VERSION 5.8 ;
BUSBITCHARS "[]" ;
DIVIDERCHAR "/" ;
UNITS
    DATABASE MICRONS 1000 ;
END UNITS

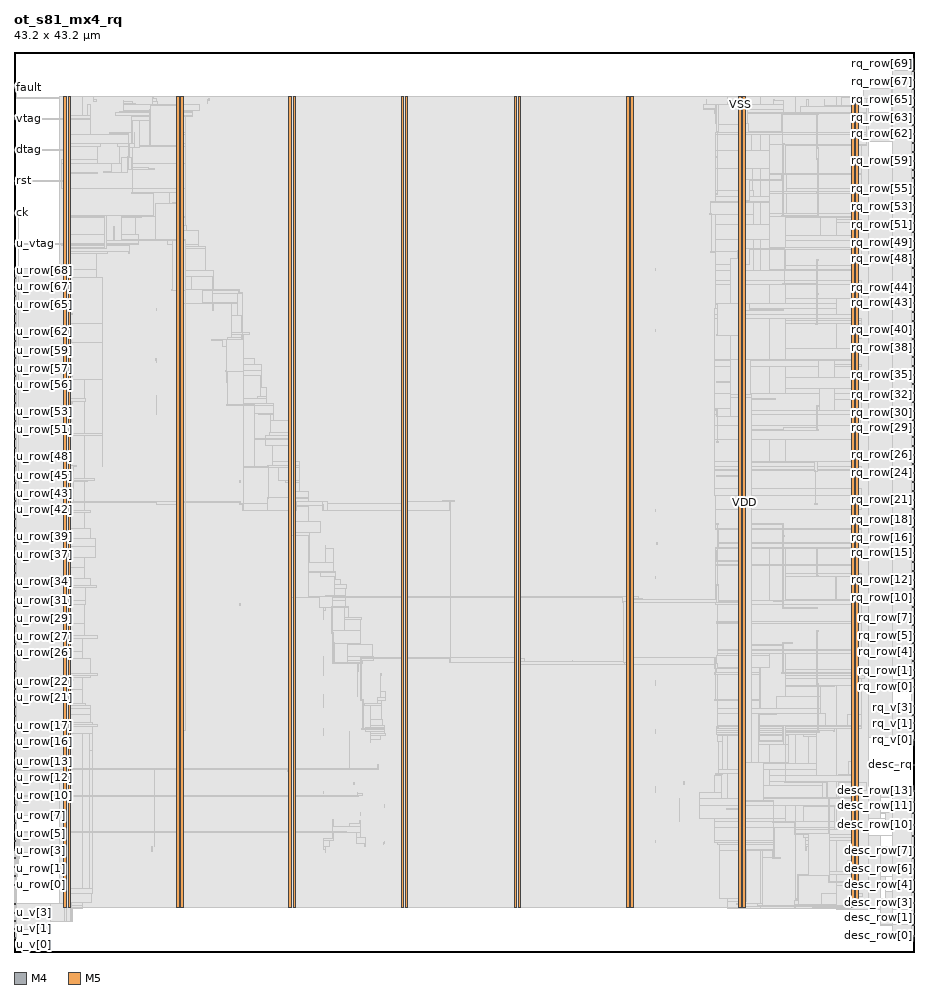
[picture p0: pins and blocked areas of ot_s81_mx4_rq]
MACRO ot_s81_mx4_rq
  FOREIGN ot_s81_mx4_rq 0 0 ;
  CLASS BLOCK ;
  SIZE 43.2 BY 43.2 ;
  PIN ck
    DIRECTION INPUT ;
    USE SIGNAL ;
    PORT
      LAYER M4 ;
        RECT  0 35.472 0.084 35.496 ;
    END
  END ck
  PIN desc_row[0]
    DIRECTION INPUT ;
    USE SIGNAL ;
    PORT
      LAYER M4 ;
        RECT  43.116 0.768 43.2 0.792 ;
    END
  END desc_row[0]
  PIN desc_row[10]
    DIRECTION INPUT ;
    USE SIGNAL ;
    PORT
      LAYER M4 ;
        RECT  43.116 6.096 43.2 6.12 ;
    END
  END desc_row[10]
  PIN desc_row[11]
    DIRECTION INPUT ;
    USE SIGNAL ;
    PORT
      LAYER M4 ;
        RECT  43.116 6.672 43.2 6.696 ;
    END
  END desc_row[11]
  PIN desc_row[12]
    DIRECTION INPUT ;
    USE SIGNAL ;
    PORT
      LAYER M4 ;
        RECT  43.116 7.2 43.2 7.224 ;
    END
  END desc_row[12]
  PIN desc_row[13]
    DIRECTION INPUT ;
    USE SIGNAL ;
    PORT
      LAYER M4 ;
        RECT  43.116 7.728 43.2 7.752 ;
    END
  END desc_row[13]
  PIN desc_row[1]
    DIRECTION INPUT ;
    USE SIGNAL ;
    PORT
      LAYER M4 ;
        RECT  43.116 1.296 43.2 1.32 ;
    END
  END desc_row[1]
  PIN desc_row[2]
    DIRECTION INPUT ;
    USE SIGNAL ;
    PORT
      LAYER M4 ;
        RECT  43.116 1.824 43.2 1.848 ;
    END
  END desc_row[2]
  PIN desc_row[3]
    DIRECTION INPUT ;
    USE SIGNAL ;
    PORT
      LAYER M4 ;
        RECT  43.116 2.352 43.2 2.376 ;
    END
  END desc_row[3]
  PIN desc_row[4]
    DIRECTION INPUT ;
    USE SIGNAL ;
    PORT
      LAYER M4 ;
        RECT  43.116 2.88 43.2 2.904 ;
    END
  END desc_row[4]
  PIN desc_row[5]
    DIRECTION INPUT ;
    USE SIGNAL ;
    PORT
      LAYER M4 ;
        RECT  43.116 3.456 43.2 3.48 ;
    END
  END desc_row[5]
  PIN desc_row[6]
    DIRECTION INPUT ;
    USE SIGNAL ;
    PORT
      LAYER M4 ;
        RECT  43.116 3.984 43.2 4.008 ;
    END
  END desc_row[6]
  PIN desc_row[7]
    DIRECTION INPUT ;
    USE SIGNAL ;
    PORT
      LAYER M4 ;
        RECT  43.116 4.512 43.2 4.536 ;
    END
  END desc_row[7]
  PIN desc_row[8]
    DIRECTION INPUT ;
    USE SIGNAL ;
    PORT
      LAYER M4 ;
        RECT  43.116 5.04 43.2 5.064 ;
    END
  END desc_row[8]
  PIN desc_row[9]
    DIRECTION INPUT ;
    USE SIGNAL ;
    PORT
      LAYER M4 ;
        RECT  43.116 5.568 43.2 5.592 ;
    END
  END desc_row[9]
  PIN desc_rq
    DIRECTION INPUT ;
    USE SIGNAL ;
    PORT
      LAYER M4 ;
        RECT  43.116 8.976 43.2 9 ;
    END
  END desc_rq
  PIN dtag
    DIRECTION OUTPUT ;
    USE SIGNAL ;
    PORT
      LAYER M4 ;
        RECT  0 38.496 0.084 38.52 ;
    END
  END dtag
  PIN fault
    DIRECTION OUTPUT ;
    USE SIGNAL ;
    PORT
      LAYER M4 ;
        RECT  0 41.472 0.084 41.496 ;
    END
  END fault
  PIN rq_row[0]
    DIRECTION OUTPUT ;
    USE SIGNAL ;
    PORT
      LAYER M4 ;
        RECT  43.116 12.72 43.2 12.744 ;
    END
  END rq_row[0]
  PIN rq_row[10]
    DIRECTION OUTPUT ;
    USE SIGNAL ;
    PORT
      LAYER M4 ;
        RECT  43.116 16.992 43.2 17.016 ;
    END
  END rq_row[10]
  PIN rq_row[11]
    DIRECTION OUTPUT ;
    USE SIGNAL ;
    PORT
      LAYER M4 ;
        RECT  43.116 17.424 43.2 17.448 ;
    END
  END rq_row[11]
  PIN rq_row[12]
    DIRECTION OUTPUT ;
    USE SIGNAL ;
    PORT
      LAYER M4 ;
        RECT  43.116 17.856 43.2 17.88 ;
    END
  END rq_row[12]
  PIN rq_row[13]
    DIRECTION OUTPUT ;
    USE SIGNAL ;
    PORT
      LAYER M4 ;
        RECT  43.116 18.288 43.2 18.312 ;
    END
  END rq_row[13]
  PIN rq_row[14]
    DIRECTION OUTPUT ;
    USE SIGNAL ;
    PORT
      LAYER M4 ;
        RECT  43.116 18.72 43.2 18.744 ;
    END
  END rq_row[14]
  PIN rq_row[15]
    DIRECTION OUTPUT ;
    USE SIGNAL ;
    PORT
      LAYER M4 ;
        RECT  43.116 19.152 43.2 19.176 ;
    END
  END rq_row[15]
  PIN rq_row[16]
    DIRECTION OUTPUT ;
    USE SIGNAL ;
    PORT
      LAYER M4 ;
        RECT  43.116 19.536 43.2 19.56 ;
    END
  END rq_row[16]
  PIN rq_row[17]
    DIRECTION OUTPUT ;
    USE SIGNAL ;
    PORT
      LAYER M4 ;
        RECT  43.116 19.968 43.2 19.992 ;
    END
  END rq_row[17]
  PIN rq_row[18]
    DIRECTION OUTPUT ;
    USE SIGNAL ;
    PORT
      LAYER M4 ;
        RECT  43.116 20.4 43.2 20.424 ;
    END
  END rq_row[18]
  PIN rq_row[19]
    DIRECTION OUTPUT ;
    USE SIGNAL ;
    PORT
      LAYER M4 ;
        RECT  43.116 20.832 43.2 20.856 ;
    END
  END rq_row[19]
  PIN rq_row[1]
    DIRECTION OUTPUT ;
    USE SIGNAL ;
    PORT
      LAYER M4 ;
        RECT  43.116 13.152 43.2 13.176 ;
    END
  END rq_row[1]
  PIN rq_row[20]
    DIRECTION OUTPUT ;
    USE SIGNAL ;
    PORT
      LAYER M4 ;
        RECT  43.116 21.264 43.2 21.288 ;
    END
  END rq_row[20]
  PIN rq_row[21]
    DIRECTION OUTPUT ;
    USE SIGNAL ;
    PORT
      LAYER M4 ;
        RECT  43.116 21.696 43.2 21.72 ;
    END
  END rq_row[21]
  PIN rq_row[22]
    DIRECTION OUTPUT ;
    USE SIGNAL ;
    PORT
      LAYER M4 ;
        RECT  43.116 22.128 43.2 22.152 ;
    END
  END rq_row[22]
  PIN rq_row[23]
    DIRECTION OUTPUT ;
    USE SIGNAL ;
    PORT
      LAYER M4 ;
        RECT  43.116 22.56 43.2 22.584 ;
    END
  END rq_row[23]
  PIN rq_row[24]
    DIRECTION OUTPUT ;
    USE SIGNAL ;
    PORT
      LAYER M4 ;
        RECT  43.116 22.992 43.2 23.016 ;
    END
  END rq_row[24]
  PIN rq_row[25]
    DIRECTION OUTPUT ;
    USE SIGNAL ;
    PORT
      LAYER M4 ;
        RECT  43.116 23.424 43.2 23.448 ;
    END
  END rq_row[25]
  PIN rq_row[26]
    DIRECTION OUTPUT ;
    USE SIGNAL ;
    PORT
      LAYER M4 ;
        RECT  43.116 23.856 43.2 23.88 ;
    END
  END rq_row[26]
  PIN rq_row[27]
    DIRECTION OUTPUT ;
    USE SIGNAL ;
    PORT
      LAYER M4 ;
        RECT  43.116 24.288 43.2 24.312 ;
    END
  END rq_row[27]
  PIN rq_row[28]
    DIRECTION OUTPUT ;
    USE SIGNAL ;
    PORT
      LAYER M4 ;
        RECT  43.116 24.72 43.2 24.744 ;
    END
  END rq_row[28]
  PIN rq_row[29]
    DIRECTION OUTPUT ;
    USE SIGNAL ;
    PORT
      LAYER M4 ;
        RECT  43.116 25.152 43.2 25.176 ;
    END
  END rq_row[29]
  PIN rq_row[2]
    DIRECTION OUTPUT ;
    USE SIGNAL ;
    PORT
      LAYER M4 ;
        RECT  43.116 13.536 43.2 13.56 ;
    END
  END rq_row[2]
  PIN rq_row[30]
    DIRECTION OUTPUT ;
    USE SIGNAL ;
    PORT
      LAYER M4 ;
        RECT  43.116 25.536 43.2 25.56 ;
    END
  END rq_row[30]
  PIN rq_row[31]
    DIRECTION OUTPUT ;
    USE SIGNAL ;
    PORT
      LAYER M4 ;
        RECT  43.116 25.968 43.2 25.992 ;
    END
  END rq_row[31]
  PIN rq_row[32]
    DIRECTION OUTPUT ;
    USE SIGNAL ;
    PORT
      LAYER M4 ;
        RECT  43.116 26.4 43.2 26.424 ;
    END
  END rq_row[32]
  PIN rq_row[33]
    DIRECTION OUTPUT ;
    USE SIGNAL ;
    PORT
      LAYER M4 ;
        RECT  43.116 26.832 43.2 26.856 ;
    END
  END rq_row[33]
  PIN rq_row[34]
    DIRECTION OUTPUT ;
    USE SIGNAL ;
    PORT
      LAYER M4 ;
        RECT  43.116 27.264 43.2 27.288 ;
    END
  END rq_row[34]
  PIN rq_row[35]
    DIRECTION OUTPUT ;
    USE SIGNAL ;
    PORT
      LAYER M4 ;
        RECT  43.116 27.696 43.2 27.72 ;
    END
  END rq_row[35]
  PIN rq_row[36]
    DIRECTION OUTPUT ;
    USE SIGNAL ;
    PORT
      LAYER M4 ;
        RECT  43.116 28.128 43.2 28.152 ;
    END
  END rq_row[36]
  PIN rq_row[37]
    DIRECTION OUTPUT ;
    USE SIGNAL ;
    PORT
      LAYER M4 ;
        RECT  43.116 28.56 43.2 28.584 ;
    END
  END rq_row[37]
  PIN rq_row[38]
    DIRECTION OUTPUT ;
    USE SIGNAL ;
    PORT
      LAYER M4 ;
        RECT  43.116 28.992 43.2 29.016 ;
    END
  END rq_row[38]
  PIN rq_row[39]
    DIRECTION OUTPUT ;
    USE SIGNAL ;
    PORT
      LAYER M4 ;
        RECT  43.116 29.424 43.2 29.448 ;
    END
  END rq_row[39]
  PIN rq_row[3]
    DIRECTION OUTPUT ;
    USE SIGNAL ;
    PORT
      LAYER M4 ;
        RECT  43.116 13.968 43.2 13.992 ;
    END
  END rq_row[3]
  PIN rq_row[40]
    DIRECTION OUTPUT ;
    USE SIGNAL ;
    PORT
      LAYER M4 ;
        RECT  43.116 29.856 43.2 29.88 ;
    END
  END rq_row[40]
  PIN rq_row[41]
    DIRECTION OUTPUT ;
    USE SIGNAL ;
    PORT
      LAYER M4 ;
        RECT  43.116 30.288 43.2 30.312 ;
    END
  END rq_row[41]
  PIN rq_row[42]
    DIRECTION OUTPUT ;
    USE SIGNAL ;
    PORT
      LAYER M4 ;
        RECT  43.116 30.72 43.2 30.744 ;
    END
  END rq_row[42]
  PIN rq_row[43]
    DIRECTION OUTPUT ;
    USE SIGNAL ;
    PORT
      LAYER M4 ;
        RECT  43.116 31.152 43.2 31.176 ;
    END
  END rq_row[43]
  PIN rq_row[44]
    DIRECTION OUTPUT ;
    USE SIGNAL ;
    PORT
      LAYER M4 ;
        RECT  43.116 31.536 43.2 31.56 ;
    END
  END rq_row[44]
  PIN rq_row[45]
    DIRECTION OUTPUT ;
    USE SIGNAL ;
    PORT
      LAYER M4 ;
        RECT  43.116 31.968 43.2 31.992 ;
    END
  END rq_row[45]
  PIN rq_row[46]
    DIRECTION OUTPUT ;
    USE SIGNAL ;
    PORT
      LAYER M4 ;
        RECT  43.116 32.4 43.2 32.424 ;
    END
  END rq_row[46]
  PIN rq_row[47]
    DIRECTION OUTPUT ;
    USE SIGNAL ;
    PORT
      LAYER M4 ;
        RECT  43.116 32.832 43.2 32.856 ;
    END
  END rq_row[47]
  PIN rq_row[48]
    DIRECTION OUTPUT ;
    USE SIGNAL ;
    PORT
      LAYER M4 ;
        RECT  43.116 33.264 43.2 33.288 ;
    END
  END rq_row[48]
  PIN rq_row[49]
    DIRECTION OUTPUT ;
    USE SIGNAL ;
    PORT
      LAYER M4 ;
        RECT  43.116 33.696 43.2 33.72 ;
    END
  END rq_row[49]
  PIN rq_row[4]
    DIRECTION OUTPUT ;
    USE SIGNAL ;
    PORT
      LAYER M4 ;
        RECT  43.116 14.4 43.2 14.424 ;
    END
  END rq_row[4]
  PIN rq_row[50]
    DIRECTION OUTPUT ;
    USE SIGNAL ;
    PORT
      LAYER M4 ;
        RECT  43.116 34.128 43.2 34.152 ;
    END
  END rq_row[50]
  PIN rq_row[51]
    DIRECTION OUTPUT ;
    USE SIGNAL ;
    PORT
      LAYER M4 ;
        RECT  43.116 34.56 43.2 34.584 ;
    END
  END rq_row[51]
  PIN rq_row[52]
    DIRECTION OUTPUT ;
    USE SIGNAL ;
    PORT
      LAYER M4 ;
        RECT  43.116 34.992 43.2 35.016 ;
    END
  END rq_row[52]
  PIN rq_row[53]
    DIRECTION OUTPUT ;
    USE SIGNAL ;
    PORT
      LAYER M4 ;
        RECT  43.116 35.424 43.2 35.448 ;
    END
  END rq_row[53]
  PIN rq_row[54]
    DIRECTION OUTPUT ;
    USE SIGNAL ;
    PORT
      LAYER M4 ;
        RECT  43.116 35.856 43.2 35.88 ;
    END
  END rq_row[54]
  PIN rq_row[55]
    DIRECTION OUTPUT ;
    USE SIGNAL ;
    PORT
      LAYER M4 ;
        RECT  43.116 36.288 43.2 36.312 ;
    END
  END rq_row[55]
  PIN rq_row[56]
    DIRECTION OUTPUT ;
    USE SIGNAL ;
    PORT
      LAYER M4 ;
        RECT  43.116 36.72 43.2 36.744 ;
    END
  END rq_row[56]
  PIN rq_row[57]
    DIRECTION OUTPUT ;
    USE SIGNAL ;
    PORT
      LAYER M4 ;
        RECT  43.116 37.152 43.2 37.176 ;
    END
  END rq_row[57]
  PIN rq_row[58]
    DIRECTION OUTPUT ;
    USE SIGNAL ;
    PORT
      LAYER M4 ;
        RECT  43.116 37.536 43.2 37.56 ;
    END
  END rq_row[58]
  PIN rq_row[59]
    DIRECTION OUTPUT ;
    USE SIGNAL ;
    PORT
      LAYER M4 ;
        RECT  43.116 37.968 43.2 37.992 ;
    END
  END rq_row[59]
  PIN rq_row[5]
    DIRECTION OUTPUT ;
    USE SIGNAL ;
    PORT
      LAYER M4 ;
        RECT  43.116 14.832 43.2 14.856 ;
    END
  END rq_row[5]
  PIN rq_row[60]
    DIRECTION OUTPUT ;
    USE SIGNAL ;
    PORT
      LAYER M4 ;
        RECT  43.116 38.4 43.2 38.424 ;
    END
  END rq_row[60]
  PIN rq_row[61]
    DIRECTION OUTPUT ;
    USE SIGNAL ;
    PORT
      LAYER M4 ;
        RECT  43.116 38.832 43.2 38.856 ;
    END
  END rq_row[61]
  PIN rq_row[62]
    DIRECTION OUTPUT ;
    USE SIGNAL ;
    PORT
      LAYER M4 ;
        RECT  43.116 39.264 43.2 39.288 ;
    END
  END rq_row[62]
  PIN rq_row[63]
    DIRECTION OUTPUT ;
    USE SIGNAL ;
    PORT
      LAYER M4 ;
        RECT  43.116 39.696 43.2 39.72 ;
    END
  END rq_row[63]
  PIN rq_row[64]
    DIRECTION OUTPUT ;
    USE SIGNAL ;
    PORT
      LAYER M4 ;
        RECT  43.116 40.128 43.2 40.152 ;
    END
  END rq_row[64]
  PIN rq_row[65]
    DIRECTION OUTPUT ;
    USE SIGNAL ;
    PORT
      LAYER M4 ;
        RECT  43.116 40.56 43.2 40.584 ;
    END
  END rq_row[65]
  PIN rq_row[66]
    DIRECTION OUTPUT ;
    USE SIGNAL ;
    PORT
      LAYER M4 ;
        RECT  43.116 40.992 43.2 41.016 ;
    END
  END rq_row[66]
  PIN rq_row[67]
    DIRECTION OUTPUT ;
    USE SIGNAL ;
    PORT
      LAYER M4 ;
        RECT  43.116 41.424 43.2 41.448 ;
    END
  END rq_row[67]
  PIN rq_row[68]
    DIRECTION OUTPUT ;
    USE SIGNAL ;
    PORT
      LAYER M4 ;
        RECT  43.116 41.856 43.2 41.88 ;
    END
  END rq_row[68]
  PIN rq_row[69]
    DIRECTION OUTPUT ;
    USE SIGNAL ;
    PORT
      LAYER M4 ;
        RECT  43.116 42.288 43.2 42.312 ;
    END
  END rq_row[69]
  PIN rq_row[6]
    DIRECTION OUTPUT ;
    USE SIGNAL ;
    PORT
      LAYER M4 ;
        RECT  43.116 15.264 43.2 15.288 ;
    END
  END rq_row[6]
  PIN rq_row[7]
    DIRECTION OUTPUT ;
    USE SIGNAL ;
    PORT
      LAYER M4 ;
        RECT  43.116 15.696 43.2 15.72 ;
    END
  END rq_row[7]
  PIN rq_row[8]
    DIRECTION OUTPUT ;
    USE SIGNAL ;
    PORT
      LAYER M4 ;
        RECT  43.116 16.128 43.2 16.152 ;
    END
  END rq_row[8]
  PIN rq_row[9]
    DIRECTION OUTPUT ;
    USE SIGNAL ;
    PORT
      LAYER M4 ;
        RECT  43.116 16.56 43.2 16.584 ;
    END
  END rq_row[9]
  PIN rq_v[0]
    DIRECTION OUTPUT ;
    USE SIGNAL ;
    PORT
      LAYER M4 ;
        RECT  43.116 10.176 43.2 10.2 ;
    END
  END rq_v[0]
  PIN rq_v[1]
    DIRECTION OUTPUT ;
    USE SIGNAL ;
    PORT
      LAYER M4 ;
        RECT  43.116 10.608 43.2 10.632 ;
    END
  END rq_v[1]
  PIN rq_v[2]
    DIRECTION OUTPUT ;
    USE SIGNAL ;
    PORT
      LAYER M4 ;
        RECT  43.116 10.992 43.2 11.016 ;
    END
  END rq_v[2]
  PIN rq_v[3]
    DIRECTION OUTPUT ;
    USE SIGNAL ;
    PORT
      LAYER M4 ;
        RECT  43.116 11.376 43.2 11.4 ;
    END
  END rq_v[3]
  PIN rq_v[4]
    DIRECTION OUTPUT ;
    USE SIGNAL ;
    PORT
      LAYER M4 ;
        RECT  43.116 11.808 43.2 11.832 ;
    END
  END rq_v[4]
  PIN rst
    DIRECTION INPUT ;
    USE SIGNAL ;
    PORT
      LAYER M4 ;
        RECT  0 37.008 0.084 37.032 ;
    END
  END rst
  PIN u_row[0]
    DIRECTION INPUT ;
    USE SIGNAL ;
    PORT
      LAYER M4 ;
        RECT  0 3.216 0.084 3.24 ;
    END
  END u_row[0]
  PIN u_row[10]
    DIRECTION INPUT ;
    USE SIGNAL ;
    PORT
      LAYER M4 ;
        RECT  0 7.488 0.084 7.512 ;
    END
  END u_row[10]
  PIN u_row[11]
    DIRECTION INPUT ;
    USE SIGNAL ;
    PORT
      LAYER M4 ;
        RECT  0 7.92 0.084 7.944 ;
    END
  END u_row[11]
  PIN u_row[12]
    DIRECTION INPUT ;
    USE SIGNAL ;
    PORT
      LAYER M4 ;
        RECT  0 8.352 0.084 8.376 ;
    END
  END u_row[12]
  PIN u_row[13]
    DIRECTION INPUT ;
    USE SIGNAL ;
    PORT
      LAYER M4 ;
        RECT  0 8.784 0.084 8.808 ;
    END
  END u_row[13]
  PIN u_row[14]
    DIRECTION INPUT ;
    USE SIGNAL ;
    PORT
      LAYER M4 ;
        RECT  0 9.216 0.084 9.24 ;
    END
  END u_row[14]
  PIN u_row[15]
    DIRECTION INPUT ;
    USE SIGNAL ;
    PORT
      LAYER M4 ;
        RECT  0 9.648 0.084 9.672 ;
    END
  END u_row[15]
  PIN u_row[16]
    DIRECTION INPUT ;
    USE SIGNAL ;
    PORT
      LAYER M4 ;
        RECT  0 10.08 0.084 10.104 ;
    END
  END u_row[16]
  PIN u_row[17]
    DIRECTION INPUT ;
    USE SIGNAL ;
    PORT
      LAYER M4 ;
        RECT  0 10.512 0.084 10.536 ;
    END
  END u_row[17]
  PIN u_row[18]
    DIRECTION INPUT ;
    USE SIGNAL ;
    PORT
      LAYER M4 ;
        RECT  0 10.896 0.084 10.92 ;
    END
  END u_row[18]
  PIN u_row[19]
    DIRECTION INPUT ;
    USE SIGNAL ;
    PORT
      LAYER M4 ;
        RECT  0 11.328 0.084 11.352 ;
    END
  END u_row[19]
  PIN u_row[1]
    DIRECTION INPUT ;
    USE SIGNAL ;
    PORT
      LAYER M4 ;
        RECT  0 3.648 0.084 3.672 ;
    END
  END u_row[1]
  PIN u_row[20]
    DIRECTION INPUT ;
    USE SIGNAL ;
    PORT
      LAYER M4 ;
        RECT  0 11.76 0.084 11.784 ;
    END
  END u_row[20]
  PIN u_row[21]
    DIRECTION INPUT ;
    USE SIGNAL ;
    PORT
      LAYER M4 ;
        RECT  0 12.192 0.084 12.216 ;
    END
  END u_row[21]
  PIN u_row[22]
    DIRECTION INPUT ;
    USE SIGNAL ;
    PORT
      LAYER M4 ;
        RECT  0 12.624 0.084 12.648 ;
    END
  END u_row[22]
  PIN u_row[23]
    DIRECTION INPUT ;
    USE SIGNAL ;
    PORT
      LAYER M4 ;
        RECT  0 13.056 0.084 13.08 ;
    END
  END u_row[23]
  PIN u_row[24]
    DIRECTION INPUT ;
    USE SIGNAL ;
    PORT
      LAYER M4 ;
        RECT  0 13.488 0.084 13.512 ;
    END
  END u_row[24]
  PIN u_row[25]
    DIRECTION INPUT ;
    USE SIGNAL ;
    PORT
      LAYER M4 ;
        RECT  0 13.92 0.084 13.944 ;
    END
  END u_row[25]
  PIN u_row[26]
    DIRECTION INPUT ;
    USE SIGNAL ;
    PORT
      LAYER M4 ;
        RECT  0 14.352 0.084 14.376 ;
    END
  END u_row[26]
  PIN u_row[27]
    DIRECTION INPUT ;
    USE SIGNAL ;
    PORT
      LAYER M4 ;
        RECT  0 14.784 0.084 14.808 ;
    END
  END u_row[27]
  PIN u_row[28]
    DIRECTION INPUT ;
    USE SIGNAL ;
    PORT
      LAYER M4 ;
        RECT  0 15.216 0.084 15.24 ;
    END
  END u_row[28]
  PIN u_row[29]
    DIRECTION INPUT ;
    USE SIGNAL ;
    PORT
      LAYER M4 ;
        RECT  0 15.648 0.084 15.672 ;
    END
  END u_row[29]
  PIN u_row[2]
    DIRECTION INPUT ;
    USE SIGNAL ;
    PORT
      LAYER M4 ;
        RECT  0 4.08 0.084 4.104 ;
    END
  END u_row[2]
  PIN u_row[30]
    DIRECTION INPUT ;
    USE SIGNAL ;
    PORT
      LAYER M4 ;
        RECT  0 16.08 0.084 16.104 ;
    END
  END u_row[30]
  PIN u_row[31]
    DIRECTION INPUT ;
    USE SIGNAL ;
    PORT
      LAYER M4 ;
        RECT  0 16.512 0.084 16.536 ;
    END
  END u_row[31]
  PIN u_row[32]
    DIRECTION INPUT ;
    USE SIGNAL ;
    PORT
      LAYER M4 ;
        RECT  0 16.896 0.084 16.92 ;
    END
  END u_row[32]
  PIN u_row[33]
    DIRECTION INPUT ;
    USE SIGNAL ;
    PORT
      LAYER M4 ;
        RECT  0 17.328 0.084 17.352 ;
    END
  END u_row[33]
  PIN u_row[34]
    DIRECTION INPUT ;
    USE SIGNAL ;
    PORT
      LAYER M4 ;
        RECT  0 17.76 0.084 17.784 ;
    END
  END u_row[34]
  PIN u_row[35]
    DIRECTION INPUT ;
    USE SIGNAL ;
    PORT
      LAYER M4 ;
        RECT  0 18.192 0.084 18.216 ;
    END
  END u_row[35]
  PIN u_row[36]
    DIRECTION INPUT ;
    USE SIGNAL ;
    PORT
      LAYER M4 ;
        RECT  0 18.624 0.084 18.648 ;
    END
  END u_row[36]
  PIN u_row[37]
    DIRECTION INPUT ;
    USE SIGNAL ;
    PORT
      LAYER M4 ;
        RECT  0 19.056 0.084 19.08 ;
    END
  END u_row[37]
  PIN u_row[38]
    DIRECTION INPUT ;
    USE SIGNAL ;
    PORT
      LAYER M4 ;
        RECT  0 19.488 0.084 19.512 ;
    END
  END u_row[38]
  PIN u_row[39]
    DIRECTION INPUT ;
    USE SIGNAL ;
    PORT
      LAYER M4 ;
        RECT  0 19.92 0.084 19.944 ;
    END
  END u_row[39]
  PIN u_row[3]
    DIRECTION INPUT ;
    USE SIGNAL ;
    PORT
      LAYER M4 ;
        RECT  0 4.512 0.084 4.536 ;
    END
  END u_row[3]
  PIN u_row[40]
    DIRECTION INPUT ;
    USE SIGNAL ;
    PORT
      LAYER M4 ;
        RECT  0 20.352 0.084 20.376 ;
    END
  END u_row[40]
  PIN u_row[41]
    DIRECTION INPUT ;
    USE SIGNAL ;
    PORT
      LAYER M4 ;
        RECT  0 20.784 0.084 20.808 ;
    END
  END u_row[41]
  PIN u_row[42]
    DIRECTION INPUT ;
    USE SIGNAL ;
    PORT
      LAYER M4 ;
        RECT  0 21.216 0.084 21.24 ;
    END
  END u_row[42]
  PIN u_row[43]
    DIRECTION INPUT ;
    USE SIGNAL ;
    PORT
      LAYER M4 ;
        RECT  0 21.648 0.084 21.672 ;
    END
  END u_row[43]
  PIN u_row[44]
    DIRECTION INPUT ;
    USE SIGNAL ;
    PORT
      LAYER M4 ;
        RECT  0 22.08 0.084 22.104 ;
    END
  END u_row[44]
  PIN u_row[45]
    DIRECTION INPUT ;
    USE SIGNAL ;
    PORT
      LAYER M4 ;
        RECT  0 22.512 0.084 22.536 ;
    END
  END u_row[45]
  PIN u_row[46]
    DIRECTION INPUT ;
    USE SIGNAL ;
    PORT
      LAYER M4 ;
        RECT  0 22.896 0.084 22.92 ;
    END
  END u_row[46]
  PIN u_row[47]
    DIRECTION INPUT ;
    USE SIGNAL ;
    PORT
      LAYER M4 ;
        RECT  0 23.328 0.084 23.352 ;
    END
  END u_row[47]
  PIN u_row[48]
    DIRECTION INPUT ;
    USE SIGNAL ;
    PORT
      LAYER M4 ;
        RECT  0 23.76 0.084 23.784 ;
    END
  END u_row[48]
  PIN u_row[49]
    DIRECTION INPUT ;
    USE SIGNAL ;
    PORT
      LAYER M4 ;
        RECT  0 24.192 0.084 24.216 ;
    END
  END u_row[49]
  PIN u_row[4]
    DIRECTION INPUT ;
    USE SIGNAL ;
    PORT
      LAYER M4 ;
        RECT  0 4.896 0.084 4.92 ;
    END
  END u_row[4]
  PIN u_row[50]
    DIRECTION INPUT ;
    USE SIGNAL ;
    PORT
      LAYER M4 ;
        RECT  0 24.624 0.084 24.648 ;
    END
  END u_row[50]
  PIN u_row[51]
    DIRECTION INPUT ;
    USE SIGNAL ;
    PORT
      LAYER M4 ;
        RECT  0 25.056 0.084 25.08 ;
    END
  END u_row[51]
  PIN u_row[52]
    DIRECTION INPUT ;
    USE SIGNAL ;
    PORT
      LAYER M4 ;
        RECT  0 25.488 0.084 25.512 ;
    END
  END u_row[52]
  PIN u_row[53]
    DIRECTION INPUT ;
    USE SIGNAL ;
    PORT
      LAYER M4 ;
        RECT  0 25.92 0.084 25.944 ;
    END
  END u_row[53]
  PIN u_row[54]
    DIRECTION INPUT ;
    USE SIGNAL ;
    PORT
      LAYER M4 ;
        RECT  0 26.352 0.084 26.376 ;
    END
  END u_row[54]
  PIN u_row[55]
    DIRECTION INPUT ;
    USE SIGNAL ;
    PORT
      LAYER M4 ;
        RECT  0 26.784 0.084 26.808 ;
    END
  END u_row[55]
  PIN u_row[56]
    DIRECTION INPUT ;
    USE SIGNAL ;
    PORT
      LAYER M4 ;
        RECT  0 27.216 0.084 27.24 ;
    END
  END u_row[56]
  PIN u_row[57]
    DIRECTION INPUT ;
    USE SIGNAL ;
    PORT
      LAYER M4 ;
        RECT  0 27.648 0.084 27.672 ;
    END
  END u_row[57]
  PIN u_row[58]
    DIRECTION INPUT ;
    USE SIGNAL ;
    PORT
      LAYER M4 ;
        RECT  0 28.08 0.084 28.104 ;
    END
  END u_row[58]
  PIN u_row[59]
    DIRECTION INPUT ;
    USE SIGNAL ;
    PORT
      LAYER M4 ;
        RECT  0 28.512 0.084 28.536 ;
    END
  END u_row[59]
  PIN u_row[5]
    DIRECTION INPUT ;
    USE SIGNAL ;
    PORT
      LAYER M4 ;
        RECT  0 5.328 0.084 5.352 ;
    END
  END u_row[5]
  PIN u_row[60]
    DIRECTION INPUT ;
    USE SIGNAL ;
    PORT
      LAYER M4 ;
        RECT  0 28.896 0.084 28.92 ;
    END
  END u_row[60]
  PIN u_row[61]
    DIRECTION INPUT ;
    USE SIGNAL ;
    PORT
      LAYER M4 ;
        RECT  0 29.328 0.084 29.352 ;
    END
  END u_row[61]
  PIN u_row[62]
    DIRECTION INPUT ;
    USE SIGNAL ;
    PORT
      LAYER M4 ;
        RECT  0 29.76 0.084 29.784 ;
    END
  END u_row[62]
  PIN u_row[63]
    DIRECTION INPUT ;
    USE SIGNAL ;
    PORT
      LAYER M4 ;
        RECT  0 30.192 0.084 30.216 ;
    END
  END u_row[63]
  PIN u_row[64]
    DIRECTION INPUT ;
    USE SIGNAL ;
    PORT
      LAYER M4 ;
        RECT  0 30.624 0.084 30.648 ;
    END
  END u_row[64]
  PIN u_row[65]
    DIRECTION INPUT ;
    USE SIGNAL ;
    PORT
      LAYER M4 ;
        RECT  0 31.056 0.084 31.08 ;
    END
  END u_row[65]
  PIN u_row[66]
    DIRECTION INPUT ;
    USE SIGNAL ;
    PORT
      LAYER M4 ;
        RECT  0 31.488 0.084 31.512 ;
    END
  END u_row[66]
  PIN u_row[67]
    DIRECTION INPUT ;
    USE SIGNAL ;
    PORT
      LAYER M4 ;
        RECT  0 31.92 0.084 31.944 ;
    END
  END u_row[67]
  PIN u_row[68]
    DIRECTION INPUT ;
    USE SIGNAL ;
    PORT
      LAYER M4 ;
        RECT  0 32.352 0.084 32.376 ;
    END
  END u_row[68]
  PIN u_row[69]
    DIRECTION INPUT ;
    USE SIGNAL ;
    PORT
      LAYER M4 ;
        RECT  0 32.784 0.084 32.808 ;
    END
  END u_row[69]
  PIN u_row[6]
    DIRECTION INPUT ;
    USE SIGNAL ;
    PORT
      LAYER M4 ;
        RECT  0 5.76 0.084 5.784 ;
    END
  END u_row[6]
  PIN u_row[7]
    DIRECTION INPUT ;
    USE SIGNAL ;
    PORT
      LAYER M4 ;
        RECT  0 6.192 0.084 6.216 ;
    END
  END u_row[7]
  PIN u_row[8]
    DIRECTION INPUT ;
    USE SIGNAL ;
    PORT
      LAYER M4 ;
        RECT  0 6.624 0.084 6.648 ;
    END
  END u_row[8]
  PIN u_row[9]
    DIRECTION INPUT ;
    USE SIGNAL ;
    PORT
      LAYER M4 ;
        RECT  0 7.056 0.084 7.08 ;
    END
  END u_row[9]
  PIN u_v[0]
    DIRECTION INPUT ;
    USE SIGNAL ;
    PORT
      LAYER M4 ;
        RECT  0 0.672 0.084 0.696 ;
    END
  END u_v[0]
  PIN u_v[1]
    DIRECTION INPUT ;
    USE SIGNAL ;
    PORT
      LAYER M4 ;
        RECT  0 1.104 0.084 1.128 ;
    END
  END u_v[1]
  PIN u_v[2]
    DIRECTION INPUT ;
    USE SIGNAL ;
    PORT
      LAYER M4 ;
        RECT  0 1.488 0.084 1.512 ;
    END
  END u_v[2]
  PIN u_v[3]
    DIRECTION INPUT ;
    USE SIGNAL ;
    PORT
      LAYER M4 ;
        RECT  0 1.872 0.084 1.896 ;
    END
  END u_v[3]
  PIN u_v[4]
    DIRECTION INPUT ;
    USE SIGNAL ;
    PORT
      LAYER M4 ;
        RECT  0 2.304 0.084 2.328 ;
    END
  END u_v[4]
  PIN u_vtag
    DIRECTION INPUT ;
    USE SIGNAL ;
    PORT
      LAYER M4 ;
        RECT  0 33.984 0.084 34.008 ;
    END
  END u_vtag
  PIN vtag
    DIRECTION OUTPUT ;
    USE SIGNAL ;
    PORT
      LAYER M4 ;
        RECT  0 39.984 0.084 40.008 ;
    END
  END vtag
  PIN VDD
    DIRECTION INOUT ;
    USE POWER ;
    PORT
      LAYER M5 ;
        RECT  40.392 2.151 40.512 41.049 ;
        RECT  34.992 2.151 35.112 41.049 ;
        RECT  29.592 2.151 29.712 41.049 ;
        RECT  24.192 2.151 24.312 41.049 ;
        RECT  18.792 2.151 18.912 41.049 ;
        RECT  13.392 2.151 13.512 41.049 ;
        RECT  7.992 2.151 8.112 41.049 ;
        RECT  2.592 2.151 2.712 41.049 ;
    END
  END VDD
  PIN VSS
    DIRECTION INOUT ;
    USE GROUND ;
    PORT
      LAYER M5 ;
        RECT  40.2 2.137 40.32 41.063 ;
        RECT  34.8 2.137 34.92 41.063 ;
        RECT  29.4 2.137 29.52 41.063 ;
        RECT  24 2.137 24.12 41.063 ;
        RECT  18.6 2.137 18.72 41.063 ;
        RECT  13.2 2.137 13.32 41.063 ;
        RECT  7.8 2.137 7.92 41.063 ;
        RECT  2.4 2.137 2.52 41.063 ;
    END
  END VSS
  OBS
    LAYER RVTN ;
     RECT  2.16 2.16 41.04 2.295 ;
     RECT  2.16 2.565 41.04 2.835 ;
     RECT  2.16 3.105 41.04 3.375 ;
     RECT  2.16 3.645 41.04 3.915 ;
     RECT  2.16 4.185 41.04 4.455 ;
     RECT  2.16 4.725 41.04 4.995 ;
     RECT  2.16 5.265 41.04 5.535 ;
     RECT  2.16 5.805 41.04 6.075 ;
     RECT  2.16 6.345 41.04 6.615 ;
     RECT  2.16 6.885 41.04 7.155 ;
     RECT  2.16 7.425 41.04 7.695 ;
     RECT  2.16 7.965 41.04 8.235 ;
     RECT  2.16 8.505 41.04 8.775 ;
     RECT  2.16 9.045 41.04 9.315 ;
     RECT  2.16 9.585 41.04 9.855 ;
     RECT  2.16 10.125 41.04 10.395 ;
     RECT  2.16 10.665 41.04 10.935 ;
     RECT  2.16 11.205 41.04 11.475 ;
     RECT  2.16 11.745 41.04 12.015 ;
     RECT  2.16 12.285 41.04 12.555 ;
     RECT  2.16 12.825 41.04 13.095 ;
     RECT  2.16 13.365 41.04 13.635 ;
     RECT  2.16 13.905 41.04 14.175 ;
     RECT  2.16 14.445 41.04 14.715 ;
     RECT  2.16 14.985 41.04 15.255 ;
     RECT  2.16 15.525 41.04 15.795 ;
     RECT  2.16 16.065 41.04 16.335 ;
     RECT  2.16 16.605 41.04 16.875 ;
     RECT  2.16 17.145 41.04 17.415 ;
     RECT  2.16 17.685 41.04 17.955 ;
     RECT  2.16 18.225 41.04 18.495 ;
     RECT  2.16 18.765 41.04 19.035 ;
     RECT  2.16 19.305 41.04 19.575 ;
     RECT  2.16 19.845 41.04 20.115 ;
     RECT  2.16 20.385 41.04 20.655 ;
     RECT  2.16 20.925 41.04 21.195 ;
     RECT  2.16 21.465 41.04 21.735 ;
     RECT  2.16 22.005 41.04 22.275 ;
     RECT  2.16 22.545 41.04 22.815 ;
     RECT  2.16 23.085 41.04 23.355 ;
     RECT  2.16 23.625 41.04 23.895 ;
     RECT  2.16 24.165 41.04 24.435 ;
     RECT  2.16 24.705 41.04 24.975 ;
     RECT  2.16 25.245 41.04 25.515 ;
     RECT  2.16 25.785 41.04 26.055 ;
     RECT  2.16 26.325 41.04 26.595 ;
     RECT  2.16 26.865 41.04 27.135 ;
     RECT  2.16 27.405 41.04 27.675 ;
     RECT  2.16 27.945 41.04 28.215 ;
     RECT  2.16 28.485 41.04 28.755 ;
     RECT  2.16 29.025 41.04 29.295 ;
     RECT  2.16 29.565 41.04 29.835 ;
     RECT  2.16 30.105 41.04 30.375 ;
     RECT  2.16 30.645 41.04 30.915 ;
     RECT  2.16 31.185 41.04 31.455 ;
     RECT  2.16 31.725 41.04 31.995 ;
     RECT  2.16 32.265 41.04 32.535 ;
     RECT  2.16 32.805 41.04 33.075 ;
     RECT  2.16 33.345 41.04 33.615 ;
     RECT  2.16 33.885 41.04 34.155 ;
     RECT  2.16 34.425 41.04 34.695 ;
     RECT  2.16 34.965 41.04 35.235 ;
     RECT  2.16 35.505 41.04 35.775 ;
     RECT  2.16 36.045 41.04 36.315 ;
     RECT  2.16 36.585 41.04 36.855 ;
     RECT  2.16 37.125 41.04 37.395 ;
     RECT  2.16 37.665 41.04 37.935 ;
     RECT  2.16 38.205 41.04 38.475 ;
     RECT  2.16 38.745 41.04 39.015 ;
     RECT  2.16 39.285 41.04 39.555 ;
     RECT  2.16 39.825 41.04 40.095 ;
     RECT  2.16 40.365 41.04 40.635 ;
     RECT  2.16 40.905 41.04 41.04 ;
    LAYER RVTP ;
     RECT  2.16 2.295 41.04 2.565 ;
     RECT  2.16 2.835 41.04 3.105 ;
     RECT  2.16 3.375 41.04 3.645 ;
     RECT  2.16 3.915 41.04 4.185 ;
     RECT  2.16 4.455 41.04 4.725 ;
     RECT  2.16 4.995 41.04 5.265 ;
     RECT  2.16 5.535 41.04 5.805 ;
     RECT  2.16 6.075 41.04 6.345 ;
     RECT  2.16 6.615 41.04 6.885 ;
     RECT  2.16 7.155 41.04 7.425 ;
     RECT  2.16 7.695 41.04 7.965 ;
     RECT  2.16 8.235 41.04 8.505 ;
     RECT  2.16 8.775 41.04 9.045 ;
     RECT  2.16 9.315 41.04 9.585 ;
     RECT  2.16 9.855 41.04 10.125 ;
     RECT  2.16 10.395 41.04 10.665 ;
     RECT  2.16 10.935 41.04 11.205 ;
     RECT  2.16 11.475 41.04 11.745 ;
     RECT  2.16 12.015 41.04 12.285 ;
     RECT  2.16 12.555 41.04 12.825 ;
     RECT  2.16 13.095 41.04 13.365 ;
     RECT  2.16 13.635 41.04 13.905 ;
     RECT  2.16 14.175 41.04 14.445 ;
     RECT  2.16 14.715 41.04 14.985 ;
     RECT  2.16 15.255 41.04 15.525 ;
     RECT  2.16 15.795 41.04 16.065 ;
     RECT  2.16 16.335 41.04 16.605 ;
     RECT  2.16 16.875 41.04 17.145 ;
     RECT  2.16 17.415 41.04 17.685 ;
     RECT  2.16 17.955 41.04 18.225 ;
     RECT  2.16 18.495 41.04 18.765 ;
     RECT  2.16 19.035 41.04 19.305 ;
     RECT  2.16 19.575 41.04 19.845 ;
     RECT  2.16 20.115 41.04 20.385 ;
     RECT  2.16 20.655 41.04 20.925 ;
     RECT  2.16 21.195 41.04 21.465 ;
     RECT  2.16 21.735 41.04 22.005 ;
     RECT  2.16 22.275 41.04 22.545 ;
     RECT  2.16 22.815 41.04 23.085 ;
     RECT  2.16 23.355 41.04 23.625 ;
     RECT  2.16 23.895 41.04 24.165 ;
     RECT  2.16 24.435 41.04 24.705 ;
     RECT  2.16 24.975 41.04 25.245 ;
     RECT  2.16 25.515 41.04 25.785 ;
     RECT  2.16 26.055 41.04 26.325 ;
     RECT  2.16 26.595 41.04 26.865 ;
     RECT  2.16 27.135 41.04 27.405 ;
     RECT  2.16 27.675 41.04 27.945 ;
     RECT  2.16 28.215 41.04 28.485 ;
     RECT  2.16 28.755 41.04 29.025 ;
     RECT  2.16 29.295 41.04 29.565 ;
     RECT  2.16 29.835 41.04 30.105 ;
     RECT  2.16 30.375 41.04 30.645 ;
     RECT  2.16 30.915 41.04 31.185 ;
     RECT  2.16 31.455 41.04 31.725 ;
     RECT  2.16 31.995 41.04 32.265 ;
     RECT  2.16 32.535 41.04 32.805 ;
     RECT  2.16 33.075 41.04 33.345 ;
     RECT  2.16 33.615 41.04 33.885 ;
     RECT  2.16 34.155 41.04 34.425 ;
     RECT  2.16 34.695 41.04 34.965 ;
     RECT  2.16 35.235 41.04 35.505 ;
     RECT  2.16 35.775 41.04 36.045 ;
     RECT  2.16 36.315 41.04 36.585 ;
     RECT  2.16 36.855 41.04 37.125 ;
     RECT  2.16 37.395 41.04 37.665 ;
     RECT  2.16 37.935 41.04 38.205 ;
     RECT  2.16 38.475 41.04 38.745 ;
     RECT  2.16 39.015 41.04 39.285 ;
     RECT  2.16 39.555 41.04 39.825 ;
     RECT  2.16 40.095 41.04 40.365 ;
     RECT  2.16 40.635 41.04 40.905 ;
    LAYER M1 ;
     RECT  2.16 2.151 41.04 41.049 ;
    LAYER M2 ;
     RECT  0.031 4.806 0.103 4.824 ;
     RECT  0.103 6.552 0.139 7.11 ;
     RECT  0.103 8.172 0.139 8.73 ;
     RECT  0.103 4.806 0.211 5.76 ;
     RECT  1.723 2.106 2.16 2.124 ;
     RECT  0.211 4.77 2.16 5.76 ;
     RECT  0.139 6.552 2.16 8.73 ;
     RECT  0.103 40.986 2.16 41.004 ;
     RECT  2.16 2.106 3.299 41.049 ;
     RECT  3.299 2.151 34.267 41.049 ;
     RECT  34.267 2.106 35.815 41.049 ;
     RECT  35.815 2.07 37.499 41.049 ;
     RECT  37.499 2.106 39.487 41.049 ;
     RECT  39.487 2.034 41.04 41.049 ;
     RECT  41.04 2.034 41.603 5.598 ;
     RECT  41.04 6.39 41.603 7.758 ;
     RECT  41.603 3.15 41.855 3.636 ;
     RECT  41.603 6.39 41.855 6.408 ;
     RECT  41.603 2.034 42.179 2.286 ;
     RECT  41.855 3.618 42.179 3.636 ;
     RECT  41.603 5.58 42.179 5.598 ;
     RECT  41.603 7.398 42.179 7.758 ;
     RECT  41.04 9.018 42.179 9.036 ;
     RECT  41.04 10.296 42.179 38.124 ;
     RECT  41.04 38.916 42.179 40.284 ;
     RECT  42.179 39.186 42.215 39.204 ;
     RECT  42.179 2.034 43.115 2.052 ;
     RECT  42.179 12.528 43.115 13.086 ;
     RECT  42.179 16.506 43.115 16.524 ;
     RECT  42.179 21.636 43.115 21.654 ;
     RECT  42.179 26.766 43.115 26.784 ;
     RECT  42.179 31.896 43.115 31.914 ;
     RECT  42.179 38.016 43.115 38.034 ;
     RECT  42.179 40.266 43.115 40.284 ;
    LAYER M3 ;
     RECT  0.108 0.667 0.126 1.003 ;
     RECT  0.036 1.003 0.126 1.037 ;
     RECT  42.156 0.763 42.174 1.291 ;
     RECT  1.728 1.099 1.746 1.867 ;
     RECT  2.772 1.483 2.79 1.867 ;
     RECT  43.092 1.819 43.11 2.057 ;
     RECT  1.728 1.867 2.79 2.101 ;
     RECT  39.492 2.029 39.51 2.101 ;
     RECT  1.728 2.101 3.294 2.129 ;
     RECT  34.272 2.101 34.29 2.143 ;
     RECT  38.304 2.101 40.158 2.143 ;
     RECT  35.82 2.065 35.838 2.191 ;
     RECT  38.304 2.143 40.305 2.191 ;
     RECT  35.82 2.191 35.946 2.203 ;
     RECT  37.476 2.065 37.494 2.203 ;
     RECT  38.232 2.191 40.305 2.203 ;
     RECT  2.304 2.129 3.294 2.255 ;
     RECT  37.332 2.203 40.305 2.255 ;
     RECT  37.476 2.255 39.474 2.291 ;
     RECT  41.58 1.291 42.174 2.291 ;
     RECT  35.676 2.203 35.946 2.333 ;
     RECT  2.415 2.255 3.294 2.371 ;
     RECT  40.215 2.255 40.305 2.371 ;
     RECT  7.815 2.143 7.905 2.413 ;
     RECT  13.215 2.143 13.305 2.413 ;
     RECT  18.615 2.143 18.705 2.413 ;
     RECT  24.015 2.143 24.105 2.413 ;
     RECT  29.415 2.143 29.505 2.413 ;
     RECT  34.272 2.143 34.905 2.413 ;
     RECT  37.476 2.291 37.674 2.489 ;
     RECT  37.548 2.489 37.674 2.525 ;
     RECT  37.548 2.525 37.638 2.561 ;
     RECT  41.58 2.291 41.85 2.561 ;
     RECT  34.272 2.413 35.154 2.569 ;
     RECT  40.215 2.371 40.554 2.641 ;
     RECT  37.584 2.561 37.638 2.759 ;
     RECT  2.415 2.371 3.726 2.803 ;
     RECT  38.772 2.291 39.474 2.831 ;
     RECT  40.215 2.641 40.734 2.831 ;
     RECT  2.415 2.803 3.762 3.029 ;
     RECT  41.832 2.561 41.85 3.173 ;
     RECT  40.215 2.831 40.554 3.181 ;
     RECT  0.036 1.037 0.054 3.211 ;
     RECT  42.156 3.451 42.174 3.641 ;
     RECT  0.036 3.211 0.126 3.643 ;
     RECT  37.62 2.759 37.638 3.685 ;
     RECT  37.62 3.685 38.178 3.713 ;
     RECT  38.16 3.713 38.178 3.721 ;
     RECT  39.492 3.181 40.554 3.721 ;
     RECT  38.16 3.721 38.322 3.725 ;
     RECT  38.304 3.725 38.322 3.839 ;
     RECT  39.096 3.721 40.554 3.875 ;
     RECT  0.036 3.643 0.162 4.075 ;
     RECT  39.996 3.875 40.554 4.415 ;
     RECT  0.036 4.075 0.198 4.507 ;
     RECT  35.928 2.333 35.946 4.531 ;
     RECT  36.756 4.495 36.774 4.531 ;
     RECT  35.928 4.531 36.774 4.541 ;
     RECT  0.036 4.507 0.234 4.829 ;
     RECT  33.876 2.569 35.154 4.885 ;
     RECT  35.928 4.541 36.486 4.885 ;
     RECT  14.94 4.765 14.958 4.927 ;
     RECT  6.624 4.801 6.642 5.063 ;
     RECT  14.832 4.927 14.958 5.071 ;
     RECT  38.016 4.891 38.034 5.071 ;
     RECT  33.876 4.885 36.486 5.161 ;
     RECT  38.016 5.071 38.322 5.161 ;
     RECT  39.096 3.875 39.114 5.161 ;
     RECT  16.848 5.071 16.866 5.197 ;
     RECT  17.712 5.161 17.73 5.197 ;
     RECT  33.768 5.161 36.486 5.233 ;
     RECT  17.712 5.197 17.802 5.261 ;
     RECT  0.108 4.829 0.234 5.297 ;
     RECT  17.784 5.261 17.802 5.297 ;
     RECT  40.215 4.415 40.554 5.297 ;
     RECT  0.108 5.297 0.162 5.333 ;
     RECT  30.78 5.233 30.798 5.333 ;
     RECT  41.58 3.979 41.598 5.333 ;
     RECT  14.832 5.071 15.138 5.341 ;
     RECT  33.624 5.233 36.486 5.341 ;
     RECT  38.016 5.161 39.114 5.341 ;
     RECT  40.215 5.297 40.497 5.341 ;
     RECT  14.832 5.341 15.318 5.459 ;
     RECT  16.452 5.197 16.866 5.495 ;
     RECT  38.016 5.341 40.497 5.503 ;
     RECT  42.156 5.563 42.174 5.603 ;
     RECT  37.872 5.503 40.497 5.659 ;
     RECT  15.3 5.459 15.318 5.755 ;
     RECT  16.452 5.495 16.614 5.755 ;
     RECT  37.476 5.659 40.497 5.873 ;
     RECT  33.624 5.341 36.522 5.971 ;
     RECT  37.476 5.873 39.402 5.971 ;
     RECT  15.3 5.755 16.614 6.035 ;
     RECT  16.092 6.035 16.614 6.179 ;
     RECT  33.624 5.971 39.402 6.275 ;
     RECT  16.596 6.179 16.614 6.305 ;
     RECT  15.3 6.035 15.318 6.341 ;
     RECT  41.832 6.091 41.85 6.413 ;
     RECT  33.624 6.275 37.026 6.421 ;
     RECT  16.632 6.547 16.65 6.719 ;
     RECT  41.58 6.667 41.598 6.845 ;
     RECT  37.872 6.275 39.402 6.961 ;
     RECT  40.215 5.873 40.497 6.961 ;
     RECT  0.108 5.333 0.126 7.051 ;
     RECT  32.904 6.421 37.026 7.051 ;
     RECT  37.872 6.961 40.497 7.051 ;
     RECT  17.784 6.925 17.802 7.079 ;
     RECT  0.108 7.051 0.162 7.115 ;
     RECT  32.904 7.051 40.497 7.349 ;
     RECT  31.932 6.241 31.95 7.385 ;
     RECT  34.776 7.349 40.497 7.421 ;
     RECT  2.415 3.029 2.697 7.483 ;
     RECT  13.215 2.413 13.497 7.483 ;
     RECT  16.488 7.483 16.506 7.501 ;
     RECT  2.304 7.483 2.697 7.529 ;
     RECT  13.104 7.483 13.497 7.529 ;
     RECT  0.144 7.115 0.162 7.619 ;
     RECT  16.488 7.501 16.722 7.619 ;
     RECT  16.488 7.619 16.506 7.655 ;
     RECT  32.904 7.349 33.966 7.655 ;
     RECT  14.832 7.591 14.85 7.727 ;
     RECT  42.156 7.195 42.174 7.763 ;
     RECT  39.564 7.421 40.497 7.771 ;
     RECT  30.78 7.663 30.798 7.961 ;
     RECT  34.776 7.421 38.826 7.997 ;
     RECT  16.308 8.041 16.326 8.159 ;
     RECT  39.564 7.771 40.914 8.159 ;
     RECT  36.252 7.997 38.826 8.167 ;
     RECT  39.564 8.159 40.497 8.167 ;
     RECT  32.148 8.041 32.166 8.195 ;
     RECT  33.624 7.655 33.966 8.465 ;
     RECT  36.252 8.167 40.497 8.465 ;
     RECT  33.696 8.465 33.966 8.509 ;
     RECT  39.564 8.465 40.497 8.537 ;
     RECT  33.696 8.509 34.002 8.545 ;
     RECT  34.776 7.997 35.442 8.545 ;
     RECT  33.696 8.545 35.442 8.573 ;
     RECT  13.215 7.529 13.497 8.671 ;
     RECT  6.732 5.071 6.75 8.699 ;
     RECT  0.108 7.915 0.126 8.735 ;
     RECT  13.14 8.671 13.497 8.771 ;
     RECT  33.804 8.573 35.442 8.771 ;
     RECT  34.815 8.771 35.442 8.779 ;
     RECT  36.252 8.465 38.538 8.779 ;
     RECT  17.46 8.779 17.478 9.005 ;
     RECT  34.815 8.779 38.538 9.041 ;
     RECT  42.156 8.971 42.174 9.041 ;
     RECT  34.815 9.041 37.17 9.077 ;
     RECT  40.068 8.537 40.497 9.149 ;
     RECT  2.415 7.529 2.697 9.211 ;
     RECT  3.636 3.029 3.762 9.661 ;
     RECT  34.815 9.077 36.27 9.979 ;
     RECT  37.008 9.077 37.17 9.979 ;
     RECT  33.804 8.771 34.002 10.084 ;
     RECT  17.1 10.057 17.118 10.201 ;
     RECT  38.124 9.041 38.538 10.363 ;
     RECT  17.1 10.201 17.586 10.399 ;
     RECT  33.768 10.084 34.002 10.399 ;
     RECT  34.815 9.979 37.17 10.399 ;
     RECT  33.768 10.399 37.17 10.435 ;
     RECT  37.908 10.363 38.538 10.435 ;
     RECT  2.304 9.211 2.697 10.471 ;
     RECT  3.6 9.661 3.762 10.471 ;
     RECT  17.1 10.399 17.838 10.499 ;
     RECT  33.732 10.435 38.538 10.555 ;
     RECT  16.092 8.743 16.11 10.589 ;
     RECT  17.1 10.499 17.766 10.597 ;
     RECT  7.815 2.413 8.097 10.633 ;
     RECT  33.732 10.555 38.574 10.633 ;
     RECT  39.348 10.597 39.366 10.633 ;
     RECT  16.884 10.597 17.766 10.669 ;
     RECT  30.78 10.471 30.798 10.697 ;
     RECT  33.732 10.633 39.366 10.705 ;
     RECT  40.215 9.149 40.497 10.705 ;
     RECT  14.832 10.399 14.85 10.733 ;
     RECT  16.704 10.669 17.766 10.733 ;
     RECT  33.732 10.705 40.554 10.741 ;
     RECT  16.884 10.733 17.766 10.769 ;
     RECT  33.732 10.741 40.698 10.829 ;
     RECT  2.304 10.471 3.762 10.831 ;
     RECT  17.136 10.769 17.766 10.895 ;
     RECT  33.768 10.829 40.698 10.895 ;
     RECT  2.304 10.831 4.014 10.931 ;
     RECT  2.304 10.931 3.762 11.039 ;
     RECT  17.136 10.895 17.694 11.165 ;
     RECT  2.304 11.039 3.69 11.399 ;
     RECT  40.032 10.895 40.698 11.399 ;
     RECT  33.768 10.895 38.934 11.435 ;
     RECT  33.768 11.435 38.718 11.669 ;
     RECT  2.304 11.399 3.654 11.705 ;
     RECT  17.136 11.165 17.622 11.821 ;
     RECT  2.34 11.705 3.654 11.849 ;
     RECT  2.34 11.849 3.438 11.939 ;
     RECT  16.812 11.821 17.622 11.939 ;
     RECT  42.156 10.171 42.174 11.939 ;
     RECT  33.768 11.669 35.802 12.055 ;
     RECT  17.46 11.939 17.622 12.091 ;
     RECT  16.668 12.055 16.686 12.125 ;
     RECT  33.732 12.055 35.802 12.125 ;
     RECT  17.46 12.091 17.838 12.209 ;
     RECT  36.576 11.669 38.718 12.281 ;
     RECT  14.832 11.749 14.85 12.353 ;
     RECT  17.568 12.209 17.838 12.515 ;
     RECT  2.34 11.939 3.294 12.619 ;
     RECT  37.008 12.281 38.718 12.757 ;
     RECT  37.008 12.757 39.366 12.793 ;
     RECT  40.215 11.399 40.698 12.793 ;
     RECT  30.78 12.793 30.798 13.019 ;
     RECT  37.008 12.793 40.698 13.135 ;
     RECT  2.304 12.619 3.294 13.171 ;
     RECT  43.092 12.523 43.11 13.181 ;
     RECT  2.304 13.171 3.654 13.261 ;
     RECT  17.568 12.515 17.586 13.261 ;
     RECT  37.008 13.135 40.842 13.289 ;
     RECT  33.768 12.125 35.802 13.333 ;
     RECT  2.304 13.261 4.014 13.361 ;
     RECT  17.568 13.261 17.658 13.361 ;
     RECT  37.008 13.289 40.698 13.369 ;
     RECT  36.9 13.369 40.698 13.421 ;
     RECT  33.624 13.333 35.802 13.433 ;
     RECT  16.488 12.253 16.506 13.441 ;
     RECT  37.008 13.421 40.698 13.559 ;
     RECT  33.732 13.433 35.802 13.639 ;
     RECT  24.015 2.413 24.297 13.801 ;
     RECT  16.488 13.441 16.542 13.837 ;
     RECT  15.912 13.837 16.722 13.901 ;
     RECT  24.015 13.801 24.498 13.909 ;
     RECT  29.415 2.413 29.697 13.909 ;
     RECT  29.376 13.909 29.697 13.915 ;
     RECT  15.984 13.901 16.722 13.981 ;
     RECT  26.784 13.909 26.802 14.009 ;
     RECT  29.232 13.915 29.697 14.071 ;
     RECT  2.304 13.361 3.654 14.099 ;
     RECT  23.832 13.909 24.498 14.099 ;
     RECT  29.232 14.071 30.366 14.135 ;
     RECT  23.832 14.099 24.297 14.141 ;
     RECT  29.304 14.135 30.366 14.141 ;
     RECT  14.832 13.261 14.85 14.207 ;
     RECT  15.984 13.981 17.262 14.207 ;
     RECT  33.732 13.639 36.27 14.243 ;
     RECT  33.768 14.243 36.27 14.341 ;
     RECT  37.008 13.559 40.497 14.341 ;
     RECT  2.304 14.099 3.294 14.405 ;
     RECT  33.768 14.341 40.497 14.485 ;
     RECT  33.768 14.485 40.554 14.521 ;
     RECT  15.984 14.207 17.19 14.783 ;
     RECT  15.984 14.783 16.614 14.827 ;
     RECT  2.415 14.405 3.294 15.061 ;
     RECT  2.415 15.061 4.014 15.179 ;
     RECT  2.415 15.179 3.402 15.211 ;
     RECT  15.3 14.827 16.614 15.449 ;
     RECT  2.304 15.211 3.402 15.755 ;
     RECT  33.768 14.521 40.698 15.787 ;
     RECT  33.732 15.787 40.698 15.863 ;
     RECT  15.876 15.449 16.614 15.961 ;
     RECT  15.876 15.961 16.686 16.061 ;
     RECT  42.156 13.531 42.174 16.259 ;
     RECT  14.832 15.961 14.85 16.411 ;
     RECT  14.832 16.411 14.958 16.537 ;
     RECT  15.876 16.061 16.038 16.537 ;
     RECT  14.832 16.537 16.038 16.555 ;
     RECT  14.652 16.555 16.038 16.565 ;
     RECT  43.092 16.501 43.11 16.589 ;
     RECT  2.415 15.755 3.402 16.681 ;
     RECT  33.768 15.863 40.698 16.681 ;
     RECT  10.836 16.609 10.854 16.709 ;
     RECT  29.415 14.141 29.697 16.795 ;
     RECT  14.652 16.565 15.894 16.871 ;
     RECT  33.696 16.681 40.698 16.877 ;
     RECT  2.415 16.681 3.438 16.891 ;
     RECT  29.415 16.795 29.934 16.891 ;
     RECT  37.044 16.877 40.698 16.907 ;
     RECT  29.415 16.891 30.186 16.979 ;
     RECT  18.615 2.413 18.897 17.032 ;
     RECT  24.015 14.141 24.297 17.035 ;
     RECT  18.615 17.032 18.99 17.069 ;
     RECT  29.415 16.979 29.97 17.069 ;
     RECT  24.015 17.035 24.39 17.075 ;
     RECT  14.94 16.871 15.894 17.105 ;
     RECT  40.215 16.907 40.698 17.141 ;
     RECT  15.408 17.105 15.894 17.455 ;
     RECT  2.304 16.891 3.438 17.491 ;
     RECT  2.304 17.491 3.978 17.609 ;
     RECT  15.408 17.455 15.966 17.645 ;
     RECT  15.408 17.645 15.678 17.879 ;
     RECT  2.304 17.609 3.69 17.951 ;
     RECT  40.215 17.141 40.497 17.995 ;
     RECT  30.78 17.923 30.798 18.023 ;
     RECT  15.408 17.879 15.426 18.031 ;
     RECT  37.044 16.907 39.438 18.031 ;
     RECT  40.215 17.995 40.554 18.031 ;
     RECT  37.044 18.031 40.698 18.185 ;
     RECT  13.215 8.771 13.497 18.229 ;
     RECT  14.724 18.031 15.426 18.229 ;
     RECT  13.215 18.229 15.426 18.257 ;
     RECT  2.304 17.951 3.366 18.455 ;
     RECT  33.696 16.877 36.27 18.565 ;
     RECT  37.044 18.185 40.497 18.565 ;
     RECT  33.696 18.565 40.497 18.605 ;
     RECT  13.215 18.257 15.354 18.689 ;
     RECT  2.34 18.455 3.366 18.931 ;
     RECT  14.94 18.689 15.354 19.373 ;
     RECT  33.696 18.605 36.27 19.381 ;
     RECT  37.008 18.605 40.497 19.381 ;
     RECT  33.696 19.381 40.497 19.409 ;
     RECT  2.34 18.931 3.906 19.483 ;
     RECT  14.94 19.373 14.958 19.499 ;
     RECT  33.804 19.409 40.497 19.615 ;
     RECT  30.852 19.543 30.87 19.643 ;
     RECT  33.804 19.615 40.554 19.651 ;
     RECT  2.304 19.483 3.906 19.841 ;
     RECT  13.215 18.689 14.202 20.155 ;
     RECT  33.804 19.651 40.698 20.281 ;
     RECT  2.304 19.841 3.654 20.309 ;
     RECT  33.66 20.281 40.698 20.345 ;
     RECT  13.215 20.155 14.706 20.651 ;
     RECT  2.304 20.309 3.402 21.091 ;
     RECT  2.304 21.091 3.69 21.191 ;
     RECT  33.66 20.345 40.554 21.235 ;
     RECT  30.78 21.163 30.798 21.263 ;
     RECT  42.156 16.987 42.174 21.299 ;
     RECT  13.215 20.651 14.13 21.361 ;
     RECT  6.84 21.499 6.858 21.629 ;
     RECT  10.836 21.499 10.854 21.629 ;
     RECT  15.012 21.499 15.03 21.629 ;
     RECT  20.556 21.595 20.574 21.631 ;
     RECT  20.556 21.631 21.114 21.677 ;
     RECT  20.556 21.677 20.574 21.695 ;
     RECT  43.092 21.631 43.11 21.725 ;
     RECT  12.996 21.361 14.13 21.775 ;
     RECT  12.816 21.775 14.13 21.821 ;
     RECT  33.66 21.235 40.698 21.901 ;
     RECT  13.215 21.821 14.13 22.109 ;
     RECT  33.624 21.901 40.698 22.235 ;
     RECT  13.215 22.109 13.698 22.549 ;
     RECT  2.304 21.191 3.402 22.585 ;
     RECT  2.304 22.585 3.51 22.621 ;
     RECT  13.032 22.549 13.698 22.621 ;
     RECT  10.836 22.549 10.854 22.649 ;
     RECT  2.304 22.621 3.87 22.739 ;
     RECT  33.624 22.235 40.497 23.125 ;
     RECT  33.624 23.125 40.554 23.161 ;
     RECT  12.672 22.621 13.698 23.275 ;
     RECT  33.624 23.161 40.698 23.315 ;
     RECT  12.168 23.275 13.698 23.351 ;
     RECT  12.42 23.351 13.698 23.549 ;
     RECT  33.624 23.315 40.554 23.549 ;
     RECT  33.624 23.549 40.497 23.555 ;
     RECT  12.42 23.549 13.497 24.331 ;
     RECT  33.624 23.555 36.27 24.601 ;
     RECT  37.008 23.555 40.497 24.601 ;
     RECT  12.06 24.331 13.497 24.619 ;
     RECT  11.484 24.619 13.497 24.665 ;
     RECT  2.304 22.739 3.402 24.781 ;
     RECT  4.248 23.323 4.266 24.781 ;
     RECT  12.06 24.665 13.497 24.809 ;
     RECT  2.304 24.781 4.266 24.899 ;
     RECT  12.276 24.809 13.497 24.935 ;
     RECT  33.624 24.601 40.497 25.285 ;
     RECT  12.312 24.935 13.497 25.511 ;
     RECT  12.312 25.511 12.438 25.789 ;
     RECT  33.624 25.285 40.626 25.789 ;
     RECT  11.736 25.789 12.438 25.861 ;
     RECT  33.624 25.789 40.698 26.015 ;
     RECT  11.448 25.861 12.438 26.251 ;
     RECT  10.836 26.251 12.438 26.321 ;
     RECT  2.304 24.899 3.402 26.401 ;
     RECT  42.156 22.123 42.174 26.429 ;
     RECT  39.384 26.015 40.698 26.519 ;
     RECT  10.836 26.321 12.114 26.555 ;
     RECT  2.304 26.401 3.438 26.591 ;
     RECT  10.836 26.555 10.854 26.599 ;
     RECT  10.728 26.599 10.854 26.663 ;
     RECT  11.7 26.555 12.114 26.663 ;
     RECT  6.84 25.789 6.858 26.699 ;
     RECT  33.624 26.015 38.646 26.789 ;
     RECT  39.384 26.519 40.662 26.789 ;
     RECT  43.092 26.761 43.11 26.861 ;
     RECT  37.008 26.789 38.646 27.031 ;
     RECT  39.384 26.789 40.497 27.031 ;
     RECT  11.808 26.663 12.114 27.095 ;
     RECT  10.728 26.663 10.818 27.355 ;
     RECT  2.304 26.591 3.402 27.481 ;
     RECT  4.248 24.899 4.266 27.481 ;
     RECT  37.008 27.031 40.497 27.599 ;
     RECT  10.188 27.355 10.818 27.607 ;
     RECT  10.188 27.607 10.998 27.679 ;
     RECT  11.808 27.095 11.898 27.679 ;
     RECT  10.188 27.679 11.898 27.917 ;
     RECT  33.624 26.789 36.27 28.111 ;
     RECT  37.008 27.599 38.61 28.111 ;
     RECT  39.384 27.599 40.497 28.111 ;
     RECT  10.368 27.917 11.898 28.211 ;
     RECT  39.384 28.111 40.698 28.211 ;
     RECT  6.84 28.291 6.858 28.381 ;
     RECT  33.624 28.111 38.61 28.381 ;
     RECT  39.384 28.211 40.497 28.381 ;
     RECT  33.624 28.381 40.497 28.451 ;
     RECT  6.804 28.381 6.858 28.481 ;
     RECT  10.368 28.211 11.538 28.481 ;
     RECT  37.044 28.451 40.497 28.985 ;
     RECT  10.368 28.481 10.818 29.083 ;
     RECT  10.008 29.083 10.818 29.219 ;
     RECT  2.304 27.481 4.266 29.255 ;
     RECT  10.26 29.219 10.818 29.371 ;
     RECT  9.504 29.371 9.522 29.408 ;
     RECT  40.215 28.985 40.497 29.461 ;
     RECT  10.26 29.371 10.926 29.489 ;
     RECT  10.44 29.489 10.926 29.515 ;
     RECT  10.44 29.515 10.998 29.641 ;
     RECT  10.44 29.641 11.322 29.759 ;
     RECT  30.78 29.803 30.798 29.903 ;
     RECT  37.044 28.985 39.474 30.181 ;
     RECT  40.215 29.461 40.698 30.181 ;
     RECT  2.415 29.255 4.266 30.187 ;
     RECT  37.044 30.181 40.698 30.335 ;
     RECT  37.044 30.335 40.662 30.407 ;
     RECT  33.624 28.451 36.27 30.415 ;
     RECT  37.044 30.407 40.497 30.415 ;
     RECT  10.44 29.759 10.926 30.569 ;
     RECT  33.624 30.415 40.497 30.605 ;
     RECT  33.624 30.605 39.474 30.875 ;
     RECT  6.84 30.811 6.858 30.911 ;
     RECT  9.54 30.811 9.558 31.117 ;
     RECT  10.44 30.569 10.71 31.117 ;
     RECT  33.66 30.875 39.474 31.145 ;
     RECT  9 31.117 10.71 31.181 ;
     RECT  40.212 30.605 40.497 31.189 ;
     RECT  37.044 31.145 39.474 31.351 ;
     RECT  40.212 31.189 40.698 31.351 ;
     RECT  7.815 10.633 8.226 31.621 ;
     RECT  9.54 31.181 10.71 31.627 ;
     RECT  7.815 31.621 8.514 31.765 ;
     RECT  9.54 31.627 10.818 31.793 ;
     RECT  7.632 31.765 8.514 31.805 ;
     RECT  10.8 31.793 10.818 31.805 ;
     RECT  43.092 31.891 43.11 31.997 ;
     RECT  33.66 31.145 36.27 32.059 ;
     RECT  37.044 31.351 40.698 32.059 ;
     RECT  33.66 32.059 40.698 32.225 ;
     RECT  2.304 30.187 4.266 32.369 ;
     RECT  7.815 31.805 8.514 32.431 ;
     RECT  9.54 31.793 9.558 32.431 ;
     RECT  7.815 32.431 9.558 32.729 ;
     RECT  33.66 32.225 40.554 32.729 ;
     RECT  2.304 32.369 3.978 32.765 ;
     RECT  36.252 32.729 40.554 32.765 ;
     RECT  30.78 32.701 30.798 32.801 ;
     RECT  37.044 32.765 40.554 32.971 ;
     RECT  2.415 32.765 3.978 33.511 ;
     RECT  2.415 33.511 4.482 33.619 ;
     RECT  5.508 33.511 5.526 33.619 ;
     RECT  36.252 32.765 36.27 33.739 ;
     RECT  37.044 32.971 40.698 33.739 ;
     RECT  7.815 32.729 9.198 33.781 ;
     RECT  36.252 33.739 40.698 33.809 ;
     RECT  7.704 33.781 9.198 33.881 ;
     RECT  2.415 33.619 5.526 33.925 ;
     RECT  2.304 33.925 5.526 33.961 ;
     RECT  7.704 33.881 8.838 33.961 ;
     RECT  2.304 33.961 5.958 34.013 ;
     RECT  37.044 33.809 40.698 34.151 ;
     RECT  33.66 32.729 35.514 34.195 ;
     RECT  36.252 33.809 36.27 34.195 ;
     RECT  37.044 34.151 40.497 34.385 ;
     RECT  2.415 34.013 5.958 34.421 ;
     RECT  7.38 33.961 8.838 34.655 ;
     RECT  7.38 34.655 8.262 34.889 ;
     RECT  33.66 34.195 36.27 34.925 ;
     RECT  39.492 34.385 40.497 35.005 ;
     RECT  39.492 35.005 40.698 35.159 ;
     RECT  7.38 34.889 8.226 35.239 ;
     RECT  2.415 34.421 5.814 35.275 ;
     RECT  37.044 34.385 38.718 35.275 ;
     RECT  39.492 35.159 40.554 35.275 ;
     RECT  2.415 35.275 6.138 35.311 ;
     RECT  7.092 35.239 8.226 35.311 ;
     RECT  36.252 34.925 36.27 35.323 ;
     RECT  37.044 35.275 40.554 35.323 ;
     RECT  33.66 34.925 35.478 35.419 ;
     RECT  36.252 35.323 40.554 35.429 ;
     RECT  33.444 35.419 35.478 35.977 ;
     RECT  36.252 35.429 36.27 35.977 ;
     RECT  33.444 35.977 36.27 36.005 ;
     RECT  33.66 36.005 36.27 36.275 ;
     RECT  36.252 36.275 36.27 36.391 ;
     RECT  37.08 35.429 40.497 36.391 ;
     RECT  36.252 36.391 40.497 36.481 ;
     RECT  36.252 36.481 40.59 36.509 ;
     RECT  33.66 36.275 35.514 36.545 ;
     RECT  2.415 35.311 8.226 36.625 ;
     RECT  37.08 36.509 40.59 36.661 ;
     RECT  36.252 36.509 36.27 37.339 ;
     RECT  37.08 36.661 40.698 37.339 ;
     RECT  36.252 37.339 40.698 37.391 ;
     RECT  33.66 36.545 35.442 37.597 ;
     RECT  36.252 37.391 36.27 37.597 ;
     RECT  2.304 36.625 8.226 37.859 ;
     RECT  2.304 37.859 4.014 38.039 ;
     RECT  43.092 38.011 43.11 38.429 ;
     RECT  33.66 37.597 36.27 38.471 ;
     RECT  5.04 37.859 8.226 38.641 ;
     RECT  2.412 38.039 4.014 38.669 ;
     RECT  2.415 38.669 4.014 38.677 ;
     RECT  37.008 37.391 40.698 38.713 ;
     RECT  36.252 38.471 36.27 38.779 ;
     RECT  37.008 38.713 40.914 38.779 ;
     RECT  2.415 38.677 4.158 38.821 ;
     RECT  4.968 38.641 8.226 38.821 ;
     RECT  42.156 27.259 42.174 39.181 ;
     RECT  33.66 38.471 35.406 39.217 ;
     RECT  36.252 38.779 40.914 39.217 ;
     RECT  2.415 38.821 8.226 39.245 ;
     RECT  4.572 39.245 8.226 39.317 ;
     RECT  4.572 39.317 4.59 39.341 ;
     RECT  33.66 39.217 40.914 39.353 ;
     RECT  42.156 39.181 42.21 39.631 ;
     RECT  2.415 39.245 3.654 39.979 ;
     RECT  2.304 39.979 3.654 40.019 ;
     RECT  5.652 39.317 8.226 40.099 ;
     RECT  5.652 40.099 8.586 40.135 ;
     RECT  2.415 40.019 3.654 40.163 ;
     RECT  33.732 39.353 40.914 40.261 ;
     RECT  4.86 40.135 8.586 40.289 ;
     RECT  33.624 40.261 40.914 40.289 ;
     RECT  43.092 40.123 43.11 40.289 ;
     RECT  5.04 40.289 8.586 40.325 ;
     RECT  5.256 40.325 8.586 40.405 ;
     RECT  33.624 40.289 36.918 40.459 ;
     RECT  42.12 39.631 42.21 40.589 ;
     RECT  37.728 40.289 40.914 40.595 ;
     RECT  38.88 40.595 40.914 40.631 ;
     RECT  3.528 40.163 3.654 40.667 ;
     RECT  5.256 40.405 8.91 40.667 ;
     RECT  33.084 40.459 36.918 40.685 ;
     RECT  6.66 40.667 8.097 40.703 ;
     RECT  8.892 40.667 8.91 40.703 ;
     RECT  33.084 40.685 35.097 40.703 ;
     RECT  35.892 40.685 36.918 40.703 ;
     RECT  5.256 40.667 5.814 40.739 ;
     RECT  2.415 40.163 2.697 40.787 ;
     RECT  7.815 40.703 8.097 40.787 ;
     RECT  13.215 25.511 13.497 40.787 ;
     RECT  18.615 17.069 18.897 40.787 ;
     RECT  24.015 17.075 24.297 40.787 ;
     RECT  29.415 17.069 29.697 40.787 ;
     RECT  34.344 40.703 35.097 40.787 ;
     RECT  5.256 40.739 5.67 40.829 ;
     RECT  6.66 40.703 6.894 40.829 ;
     RECT  5.256 40.829 5.274 40.865 ;
     RECT  34.344 40.787 34.905 40.865 ;
     RECT  36.468 40.703 36.918 40.865 ;
     RECT  9.288 40.711 9.306 40.873 ;
     RECT  3.816 40.801 3.942 40.901 ;
     RECT  9.288 40.873 9.378 40.901 ;
     RECT  33.228 40.703 33.246 40.901 ;
     RECT  36.468 40.865 36.486 40.901 ;
     RECT  38.052 40.595 38.142 40.901 ;
     RECT  38.88 40.631 38.898 40.901 ;
     RECT  38.052 40.901 38.07 40.937 ;
     RECT  6.66 40.829 6.858 40.973 ;
     RECT  9.36 40.901 9.378 40.973 ;
     RECT  3.816 40.901 3.834 41.009 ;
     RECT  6.66 40.973 6.678 41.009 ;
     RECT  39.708 40.631 40.914 41.009 ;
     RECT  40.215 41.009 40.914 41.021 ;
     RECT  2.415 40.787 2.505 41.057 ;
     RECT  7.815 40.787 7.905 41.057 ;
     RECT  13.215 40.787 13.305 41.057 ;
     RECT  18.615 40.787 18.705 41.057 ;
     RECT  24.015 40.787 24.105 41.057 ;
     RECT  29.415 40.787 29.505 41.057 ;
     RECT  34.815 40.865 34.905 41.057 ;
     RECT  40.215 41.021 40.806 41.057 ;
     RECT  40.788 41.057 40.806 41.453 ;
     RECT  0.108 40.981 0.126 41.501 ;
     RECT  42.12 40.589 42.174 41.885 ;
     RECT  42.156 41.885 42.174 42.317 ;
    LAYER M4 ;
     RECT  0.025 1.008 0.06 1.032 ;
     RECT  0.06 0.672 0.137 32.808 ;
     RECT  0.06 41.472 0.137 41.496 ;
     RECT  0.137 3.648 0.173 5.784 ;
     RECT  0.137 7.056 0.173 7.512 ;
     RECT  0.173 4.08 0.209 5.784 ;
     RECT  0.06 35.472 0.227 35.496 ;
     RECT  0.209 4.512 0.245 5.784 ;
     RECT  0.137 1.104 1.757 2.328 ;
     RECT  0.06 37.008 2.365 37.032 ;
     RECT  1.757 1.488 2.408 2.328 ;
     RECT  0.245 5.76 2.408 5.784 ;
     RECT  0.173 7.488 2.408 7.512 ;
     RECT  0.137 8.784 2.408 32.808 ;
     RECT  0.06 33.984 2.408 34.008 ;
     RECT  2.365 37.008 2.408 37.416 ;
     RECT  0.06 38.496 2.408 38.52 ;
     RECT  0.06 39.984 2.408 40.008 ;
     RECT  2.408 1.488 2.512 41.052 ;
     RECT  2.512 1.488 2.704 40.782 ;
     RECT  2.704 1.488 2.765 2.328 ;
     RECT  2.704 25.488 2.765 26.376 ;
     RECT  2.704 29.328 2.765 29.352 ;
     RECT  2.765 1.488 2.801 1.512 ;
     RECT  2.765 26.352 2.801 26.376 ;
     RECT  2.704 27.648 2.801 27.672 ;
     RECT  2.704 30.624 2.801 30.648 ;
     RECT  2.704 13.056 2.837 13.08 ;
     RECT  2.704 21.6 2.837 23.352 ;
     RECT  2.837 23.328 2.981 23.352 ;
     RECT  2.704 37.392 4.025 37.416 ;
     RECT  2.704 33.792 4.345 33.816 ;
     RECT  2.704 35.328 4.345 35.352 ;
     RECT  4.345 33.792 4.457 35.352 ;
     RECT  4.309 37.44 4.669 37.464 ;
     RECT  4.669 37.44 5.173 37.848 ;
     RECT  4.457 34.176 5.177 35.352 ;
     RECT  5.173 37.44 5.425 38.136 ;
     RECT  5.425 37.44 5.465 38.184 ;
     RECT  5.465 37.584 5.509 38.184 ;
     RECT  4.561 39.312 5.509 39.336 ;
     RECT  5.509 37.584 5.641 39.336 ;
     RECT  5.641 37.584 5.699 39.912 ;
     RECT  5.699 38.64 6.041 39.912 ;
     RECT  5.699 37.584 6.437 37.656 ;
     RECT  6.041 38.736 6.505 39.912 ;
     RECT  6.505 38.736 6.541 40.44 ;
     RECT  5.177 35.328 6.716 35.352 ;
     RECT  5.653 36.432 6.716 36.456 ;
     RECT  6.437 37.584 6.725 37.608 ;
     RECT  2.837 21.6 6.829 21.624 ;
     RECT  6.716 35.328 7.477 36.456 ;
     RECT  2.704 5.76 7.808 5.784 ;
     RECT  2.704 7.488 7.808 7.512 ;
     RECT  2.704 8.784 7.808 8.808 ;
     RECT  6.829 21.504 7.808 21.624 ;
     RECT  7.58 31.776 7.808 31.8 ;
     RECT  5.177 34.176 7.808 34.2 ;
     RECT  7.477 35.28 7.808 36.456 ;
     RECT  6.541 38.736 7.808 40.632 ;
     RECT  7.808 2.148 7.912 41.052 ;
     RECT  7.912 2.418 8.104 40.782 ;
     RECT  8.104 31.152 8.243 32.616 ;
     RECT  8.104 34.176 8.243 34.2 ;
     RECT  8.243 31.152 9.029 31.8 ;
     RECT  9.493 29.376 9.997 29.4 ;
     RECT  10.165 27.888 10.177 27.912 ;
     RECT  10.177 27.36 10.252 27.912 ;
     RECT  10.252 27.36 10.261 27.384 ;
     RECT  10.213 26.256 10.717 26.28 ;
     RECT  9.029 31.776 10.789 31.8 ;
     RECT  8.104 21.6 10.825 21.624 ;
     RECT  10.717 26.256 10.829 26.76 ;
     RECT  9.997 29.088 10.829 29.4 ;
     RECT  10.789 31.632 10.829 31.8 ;
     RECT  10.825 21.504 10.865 21.624 ;
     RECT  10.829 29.376 10.925 29.4 ;
     RECT  10.925 29.376 10.937 29.64 ;
     RECT  10.829 31.632 10.979 31.656 ;
     RECT  10.865 21.504 10.981 21.528 ;
     RECT  10.937 29.52 11.009 29.64 ;
     RECT  11.009 29.52 11.027 29.544 ;
     RECT  11.468 24.624 11.555 24.648 ;
     RECT  10.829 26.256 11.555 26.28 ;
     RECT  10.981 21.216 12.181 21.528 ;
     RECT  11.509 23.28 12.227 23.304 ;
     RECT  8.104 5.76 13.208 5.784 ;
     RECT  8.104 7.488 13.208 7.512 ;
     RECT  8.104 8.784 13.208 8.808 ;
     RECT  12.181 21.216 13.208 21.816 ;
     RECT  13.208 2.148 13.312 41.052 ;
     RECT  13.312 2.418 13.504 40.782 ;
     RECT  13.504 21.216 13.565 21.624 ;
     RECT  13.504 18.528 14.147 18.552 ;
     RECT  13.504 19.968 14.147 19.992 ;
     RECT  13.504 17.04 14.641 17.064 ;
     RECT  13.565 21.456 14.821 21.624 ;
     RECT  14.821 21.216 15.041 21.624 ;
     RECT  15.253 15.312 15.289 15.336 ;
     RECT  14.641 16.56 15.299 17.064 ;
     RECT  15.289 14.832 15.301 15.336 ;
     RECT  15.301 13.872 15.34 15.336 ;
     RECT  15.34 13.872 15.373 14.856 ;
     RECT  13.504 5.76 15.941 5.784 ;
     RECT  13.504 7.488 16.517 7.512 ;
     RECT  15.373 13.872 16.645 13.896 ;
     RECT  16.645 13.872 16.691 14.136 ;
     RECT  16.693 10.704 16.787 10.728 ;
     RECT  16.645 12.096 16.787 12.12 ;
     RECT  13.504 8.784 17.489 8.808 ;
     RECT  16.691 14.112 18.608 14.136 ;
     RECT  15.299 17.04 18.608 17.064 ;
     RECT  15.041 21.216 18.608 21.528 ;
     RECT  18.608 2.148 18.712 41.052 ;
     RECT  18.712 2.418 18.904 40.782 ;
     RECT  18.904 14.112 20.917 14.136 ;
     RECT  18.904 21.216 20.917 21.624 ;
     RECT  20.917 21.216 20.963 21.672 ;
     RECT  20.963 21.648 21.125 21.672 ;
     RECT  20.917 13.92 24.008 14.136 ;
     RECT  18.904 17.04 24.008 17.064 ;
     RECT  24.008 2.148 24.112 41.052 ;
     RECT  24.112 2.418 24.304 40.782 ;
     RECT  24.304 17.04 29.221 17.064 ;
     RECT  24.304 13.824 29.293 13.944 ;
     RECT  29.293 13.824 29.408 14.136 ;
     RECT  29.221 16.8 29.408 17.064 ;
     RECT  29.408 2.148 29.512 41.052 ;
     RECT  29.512 2.418 29.704 40.782 ;
     RECT  33.404 35.424 33.491 35.448 ;
     RECT  29.704 13.824 33.637 14.136 ;
     RECT  33.445 33.6 33.649 33.624 ;
     RECT  33.637 13.632 33.683 14.136 ;
     RECT  33.073 40.464 33.685 40.488 ;
     RECT  29.704 16.8 33.721 16.92 ;
     RECT  33.685 39.792 33.721 40.68 ;
     RECT  33.692 19.248 33.733 19.272 ;
     RECT  33.692 26.064 33.733 26.088 ;
     RECT  33.683 13.632 33.761 13.848 ;
     RECT  33.733 18.768 33.779 19.272 ;
     RECT  33.692 36.384 33.779 36.408 ;
     RECT  33.692 38.16 33.779 38.184 ;
     RECT  33.721 10.8 33.805 10.824 ;
     RECT  33.721 16.8 33.805 17.64 ;
     RECT  33.721 20.544 33.805 20.568 ;
     RECT  33.721 24.48 33.805 24.504 ;
     RECT  33.721 29.616 33.805 29.64 ;
     RECT  33.721 39.36 33.805 40.68 ;
     RECT  33.637 12.096 33.825 12.12 ;
     RECT  33.733 25.728 34.405 26.088 ;
     RECT  33.721 27.36 34.405 27.384 ;
     RECT  33.649 33.024 34.729 33.624 ;
     RECT  34.693 2.304 34.808 2.328 ;
     RECT  34.189 6.864 34.808 6.888 ;
     RECT  33.761 13.632 34.808 13.656 ;
     RECT  33.721 15.792 34.808 15.816 ;
     RECT  33.805 16.8 34.808 16.824 ;
     RECT  33.779 18.768 34.808 18.792 ;
     RECT  33.721 22.848 34.808 22.872 ;
     RECT  34.405 25.728 34.808 27.384 ;
     RECT  33.649 31.104 34.808 31.128 ;
     RECT  34.729 33.024 34.808 33.672 ;
     RECT  33.805 39.744 34.808 40.68 ;
     RECT  34.808 2.148 34.912 41.052 ;
     RECT  34.912 2.208 35.104 40.782 ;
     RECT  35.104 39.36 35.201 40.68 ;
     RECT  35.201 39.36 35.267 39.768 ;
     RECT  35.104 13.632 35.309 13.656 ;
     RECT  35.104 15.792 35.309 15.816 ;
     RECT  35.104 18.768 35.309 18.792 ;
     RECT  35.104 22.848 35.309 23.544 ;
     RECT  35.104 30.816 35.309 31.128 ;
     RECT  35.104 33.024 35.309 33.768 ;
     RECT  35.104 25.056 35.315 27.336 ;
     RECT  35.104 36.096 35.315 37.08 ;
     RECT  35.315 26.544 35.363 27.336 ;
     RECT  35.104 16.8 35.381 16.92 ;
     RECT  35.381 16.896 35.411 16.92 ;
     RECT  35.363 26.544 35.411 26.76 ;
     RECT  35.104 2.208 35.705 2.328 ;
     RECT  35.104 9.072 35.741 11.448 ;
     RECT  35.741 10.128 35.777 11.448 ;
     RECT  35.741 9.072 36.065 9.096 ;
     RECT  35.104 4.896 36.421 4.92 ;
     RECT  36.421 4.512 36.467 4.92 ;
     RECT  35.104 7.248 36.467 7.272 ;
     RECT  35.411 26.544 36.533 26.568 ;
     RECT  35.777 11.424 36.605 11.448 ;
     RECT  36.467 4.512 36.785 4.536 ;
     RECT  35.267 39.36 36.853 39.384 ;
     RECT  35.315 37.056 36.86 37.08 ;
     RECT  35.104 14.736 36.881 14.76 ;
     RECT  35.777 10.128 36.889 10.152 ;
     RECT  35.104 20.544 36.889 20.568 ;
     RECT  36.853 39.36 36.889 40.248 ;
     RECT  36.889 38.784 36.893 40.248 ;
     RECT  36.457 16.848 36.901 16.872 ;
     RECT  35.315 25.056 36.925 25.08 ;
     RECT  36.889 19.968 36.929 20.568 ;
     RECT  35.309 30.816 36.929 30.84 ;
     RECT  36.86 13.392 36.947 13.416 ;
     RECT  36.881 14.736 36.947 14.856 ;
     RECT  36.901 16.512 36.947 16.872 ;
     RECT  36.86 37.056 36.947 37.368 ;
     RECT  36.889 10.128 36.956 10.872 ;
     RECT  36.929 19.968 36.973 19.992 ;
     RECT  36.893 38.784 36.973 38.808 ;
     RECT  35.309 33.744 36.995 33.768 ;
     RECT  36.956 9.984 37.043 10.872 ;
     RECT  36.947 14.832 37.361 14.856 ;
     RECT  36.421 6.24 37.465 6.264 ;
     RECT  37.465 5.664 37.505 6.264 ;
     RECT  35.705 2.208 37.685 2.232 ;
     RECT  38.108 3.696 38.195 3.72 ;
     RECT  35.309 23.52 38.437 23.544 ;
     RECT  37.505 5.664 38.441 5.688 ;
     RECT  36.861 18.576 38.509 18.6 ;
     RECT  38.509 18.576 38.533 19.416 ;
     RECT  36.911 32.064 38.533 32.088 ;
     RECT  38.533 38.592 38.54 38.616 ;
     RECT  38.533 12.864 38.545 12.888 ;
     RECT  36.947 16.512 38.549 16.536 ;
     RECT  38.437 21.504 38.549 21.528 ;
     RECT  35.104 28.416 38.549 28.44 ;
     RECT  38.533 18.048 38.579 19.416 ;
     RECT  36.925 25.056 38.579 25.176 ;
     RECT  38.492 30.144 38.579 30.168 ;
     RECT  38.533 31.584 38.579 32.088 ;
     RECT  38.437 23.088 38.585 23.544 ;
     RECT  38.509 15.408 38.593 15.432 ;
     RECT  38.579 19.392 38.593 19.416 ;
     RECT  38.509 26.208 38.593 26.232 ;
     RECT  38.545 12.528 38.62 12.888 ;
     RECT  38.579 18.048 38.62 18.072 ;
     RECT  38.579 25.056 38.62 25.08 ;
     RECT  38.579 31.584 38.62 31.608 ;
     RECT  38.533 33.216 38.62 33.24 ;
     RECT  38.54 38.064 38.62 38.616 ;
     RECT  36.893 40.224 38.62 40.248 ;
     RECT  38.54 36.48 38.627 36.504 ;
     RECT  38.62 38.064 38.627 38.088 ;
     RECT  38.62 12.528 38.629 12.552 ;
     RECT  36.861 35.328 38.629 35.352 ;
     RECT  37.043 10.56 38.649 10.584 ;
     RECT  36.997 8.16 39.013 8.184 ;
     RECT  39.013 7.392 39.059 8.184 ;
     RECT  39.059 7.392 39.155 7.416 ;
     RECT  39.109 3.36 40.208 3.384 ;
     RECT  40.208 2.148 40.312 41.052 ;
     RECT  40.312 2.418 40.504 41.052 ;
     RECT  40.504 40.992 40.777 41.052 ;
     RECT  41.569 2.352 41.821 2.376 ;
     RECT  41.569 6.672 41.821 6.696 ;
     RECT  40.777 40.992 42.109 41.448 ;
     RECT  41.569 1.296 42.145 1.32 ;
     RECT  41.821 2.352 42.145 2.904 ;
     RECT  41.569 3.984 42.145 5.064 ;
     RECT  41.821 6.096 42.145 6.696 ;
     RECT  42.109 40.992 42.145 41.88 ;
     RECT  42.145 13.536 42.181 39.72 ;
     RECT  42.145 40.992 42.181 42.312 ;
     RECT  42.145 0.768 43.081 1.32 ;
     RECT  42.145 2.352 43.081 7.752 ;
     RECT  42.145 10.176 43.081 11.832 ;
     RECT  42.181 13.536 43.081 42.312 ;
     RECT  43.081 0.768 43.164 7.752 ;
     RECT  42.145 8.976 43.164 9 ;
     RECT  43.081 10.176 43.164 42.312 ;
    LAYER M5 ;
     RECT  2.4 2.137 2.52 2.151 ;
     RECT  7.8 2.137 7.92 2.151 ;
     RECT  13.2 2.137 13.32 2.151 ;
     RECT  18.6 2.137 18.72 2.151 ;
     RECT  24 2.137 24.12 2.151 ;
     RECT  29.4 2.137 29.52 2.151 ;
     RECT  34.8 2.137 34.92 2.151 ;
     RECT  40.2 2.137 40.32 2.151 ;
     RECT  39.12 3.349 39.144 3.685 ;
     RECT  38.16 3.685 39.144 5.699 ;
     RECT  34.8 2.151 35.112 7.237 ;
     RECT  36.432 4.501 36.456 7.237 ;
     RECT  34.8 7.237 36.456 7.283 ;
     RECT  39.12 5.699 39.144 7.381 ;
     RECT  39.024 7.381 39.144 7.427 ;
     RECT  39.024 7.427 39.048 8.195 ;
     RECT  34.8 7.283 35.976 9.107 ;
     RECT  37.008 8.149 37.032 10.883 ;
     RECT  16.752 10.693 16.776 12.085 ;
     RECT  33.744 10.789 33.768 12.085 ;
     RECT  16.656 12.085 16.776 12.131 ;
     RECT  33.648 12.085 33.768 12.131 ;
     RECT  38.592 10.549 38.616 12.563 ;
     RECT  29.4 2.151 29.712 13.909 ;
     RECT  16.656 12.131 16.68 14.147 ;
     RECT  33.648 12.131 33.672 14.147 ;
     RECT  15.312 13.861 15.336 14.867 ;
     RECT  36.912 13.381 36.936 14.867 ;
     RECT  38.544 12.853 38.568 15.443 ;
     RECT  15.264 15.301 15.288 16.595 ;
     RECT  29.232 13.909 29.712 16.835 ;
     RECT  13.2 2.151 13.512 17.029 ;
     RECT  38.544 18.037 38.568 19.427 ;
     RECT  13.2 17.029 14.136 20.003 ;
     RECT  36.912 16.501 36.936 20.003 ;
     RECT  33.744 17.605 33.768 20.579 ;
     RECT  14.832 21.205 14.856 21.491 ;
     RECT  20.928 13.909 20.952 21.683 ;
     RECT  38.448 21.493 38.472 23.123 ;
     RECT  10.992 21.205 11.016 23.269 ;
     RECT  12.192 21.781 12.216 23.269 ;
     RECT  10.992 23.269 12.216 23.315 ;
     RECT  33.744 24.469 33.768 26.099 ;
     RECT  38.544 25.045 38.568 26.243 ;
     RECT  10.992 23.315 11.544 26.245 ;
     RECT  10.224 26.245 11.544 26.291 ;
     RECT  34.8 9.107 35.4 26.629 ;
     RECT  34.416 26.629 35.4 26.771 ;
     RECT  10.224 26.291 11.016 27.877 ;
     RECT  34.416 26.771 35.352 28.451 ;
     RECT  10.176 27.877 11.016 29.411 ;
     RECT  10.944 29.411 11.016 29.555 ;
     RECT  34.416 28.451 35.112 29.605 ;
     RECT  33.744 29.605 35.112 31.139 ;
     RECT  7.8 2.151 8.112 31.141 ;
     RECT  10.944 29.555 10.968 31.667 ;
     RECT  7.8 31.141 8.232 31.765 ;
     RECT  38.544 30.133 38.568 33.251 ;
     RECT  34.416 31.139 35.112 33.299 ;
     RECT  36.96 32.053 36.984 33.779 ;
     RECT  7.632 31.765 8.232 34.165 ;
     RECT  6.768 34.165 8.232 34.211 ;
     RECT  4.8 34.165 4.824 34.835 ;
     RECT  33.456 33.589 33.48 35.459 ;
     RECT  0.192 21.493 0.216 35.507 ;
     RECT  6.768 34.211 8.112 35.939 ;
     RECT  7.632 35.939 8.112 35.987 ;
     RECT  34.8 33.299 35.112 36.085 ;
     RECT  34.8 36.085 35.304 37.091 ;
     RECT  38.592 35.317 38.616 38.099 ;
     RECT  5.664 36.421 5.688 38.149 ;
     RECT  5.52 38.149 5.688 38.629 ;
     RECT  5.52 38.629 5.784 38.819 ;
     RECT  36.912 35.317 36.936 38.819 ;
     RECT  5.76 38.819 5.784 39.347 ;
     RECT  34.8 37.091 35.112 39.349 ;
     RECT  33.744 36.373 33.768 39.395 ;
     RECT  34.8 39.349 35.256 39.779 ;
     RECT  38.544 38.581 38.568 40.259 ;
     RECT  33.696 39.781 33.72 40.691 ;
     RECT  2.4 2.151 2.712 41.049 ;
     RECT  7.8 35.987 8.112 41.049 ;
     RECT  13.2 20.003 13.512 41.049 ;
     RECT  18.6 2.151 18.912 41.049 ;
     RECT  24 2.151 24.312 41.049 ;
     RECT  29.4 16.835 29.712 41.049 ;
     RECT  34.8 39.779 35.112 41.049 ;
     RECT  40.2 2.151 40.512 41.049 ;
     RECT  2.4 41.049 2.52 41.063 ;
     RECT  7.8 41.049 7.92 41.063 ;
     RECT  13.2 41.049 13.32 41.063 ;
     RECT  18.6 41.049 18.72 41.063 ;
     RECT  24 41.049 24.12 41.063 ;
     RECT  29.4 41.049 29.52 41.063 ;
     RECT  34.8 41.049 34.92 41.063 ;
     RECT  40.2 41.049 40.32 41.063 ;
  END
END ot_s81_mx4_rq
END LIBRARY
